VERSION 5.7 ;
BUSBITCHARS "[]" ;
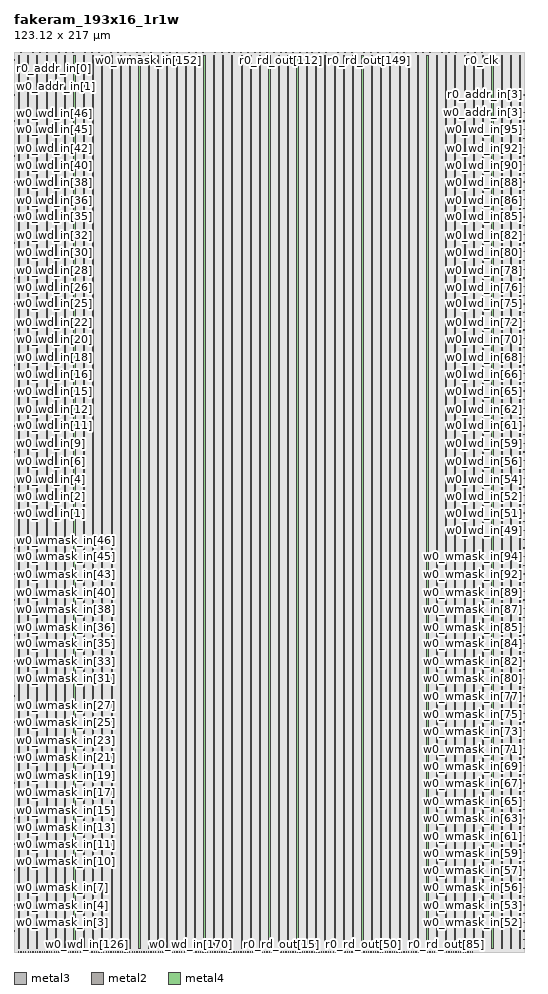
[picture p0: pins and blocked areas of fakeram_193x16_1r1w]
MACRO fakeram_193x16_1r1w
  FOREIGN fakeram_193x16_1r1w 0 0 ;
  SYMMETRY X Y R90 ;
  SIZE 123.120 BY 217.000 ;
  CLASS BLOCK ;
  PIN w0_wmask_in[0]
    DIRECTION INPUT ;
    USE SIGNAL ;
    SHAPE ABUTMENT ;
    PORT
      LAYER metal3 ;
      RECT 0.000 0.805 0.210 0.875 ;
    END
  END w0_wmask_in[0]
  PIN w0_wmask_in[1]
    DIRECTION INPUT ;
    USE SIGNAL ;
    SHAPE ABUTMENT ;
    PORT
      LAYER metal3 ;
      RECT 0.000 2.905 0.210 2.975 ;
    END
  END w0_wmask_in[1]
  PIN w0_wmask_in[2]
    DIRECTION INPUT ;
    USE SIGNAL ;
    SHAPE ABUTMENT ;
    PORT
      LAYER metal3 ;
      RECT 0.000 5.005 0.210 5.075 ;
    END
  END w0_wmask_in[2]
  PIN w0_wmask_in[3]
    DIRECTION INPUT ;
    USE SIGNAL ;
    SHAPE ABUTMENT ;
    PORT
      LAYER metal3 ;
      RECT 0.000 7.105 0.210 7.175 ;
    END
  END w0_wmask_in[3]
  PIN w0_wmask_in[4]
    DIRECTION INPUT ;
    USE SIGNAL ;
    SHAPE ABUTMENT ;
    PORT
      LAYER metal3 ;
      RECT 0.000 9.205 0.210 9.275 ;
    END
  END w0_wmask_in[4]
  PIN w0_wmask_in[5]
    DIRECTION INPUT ;
    USE SIGNAL ;
    SHAPE ABUTMENT ;
    PORT
      LAYER metal3 ;
      RECT 0.000 11.305 0.210 11.375 ;
    END
  END w0_wmask_in[5]
  PIN w0_wmask_in[6]
    DIRECTION INPUT ;
    USE SIGNAL ;
    SHAPE ABUTMENT ;
    PORT
      LAYER metal3 ;
      RECT 0.000 13.405 0.210 13.475 ;
    END
  END w0_wmask_in[6]
  PIN w0_wmask_in[7]
    DIRECTION INPUT ;
    USE SIGNAL ;
    SHAPE ABUTMENT ;
    PORT
      LAYER metal3 ;
      RECT 0.000 15.505 0.210 15.575 ;
    END
  END w0_wmask_in[7]
  PIN w0_wmask_in[8]
    DIRECTION INPUT ;
    USE SIGNAL ;
    SHAPE ABUTMENT ;
    PORT
      LAYER metal3 ;
      RECT 0.000 17.605 0.210 17.675 ;
    END
  END w0_wmask_in[8]
  PIN w0_wmask_in[9]
    DIRECTION INPUT ;
    USE SIGNAL ;
    SHAPE ABUTMENT ;
    PORT
      LAYER metal3 ;
      RECT 0.000 19.705 0.210 19.775 ;
    END
  END w0_wmask_in[9]
  PIN w0_wmask_in[10]
    DIRECTION INPUT ;
    USE SIGNAL ;
    SHAPE ABUTMENT ;
    PORT
      LAYER metal3 ;
      RECT 0.000 21.805 0.210 21.875 ;
    END
  END w0_wmask_in[10]
  PIN w0_wmask_in[11]
    DIRECTION INPUT ;
    USE SIGNAL ;
    SHAPE ABUTMENT ;
    PORT
      LAYER metal3 ;
      RECT 0.000 23.905 0.210 23.975 ;
    END
  END w0_wmask_in[11]
  PIN w0_wmask_in[12]
    DIRECTION INPUT ;
    USE SIGNAL ;
    SHAPE ABUTMENT ;
    PORT
      LAYER metal3 ;
      RECT 0.000 26.005 0.210 26.075 ;
    END
  END w0_wmask_in[12]
  PIN w0_wmask_in[13]
    DIRECTION INPUT ;
    USE SIGNAL ;
    SHAPE ABUTMENT ;
    PORT
      LAYER metal3 ;
      RECT 0.000 28.105 0.210 28.175 ;
    END
  END w0_wmask_in[13]
  PIN w0_wmask_in[14]
    DIRECTION INPUT ;
    USE SIGNAL ;
    SHAPE ABUTMENT ;
    PORT
      LAYER metal3 ;
      RECT 0.000 30.205 0.210 30.275 ;
    END
  END w0_wmask_in[14]
  PIN w0_wmask_in[15]
    DIRECTION INPUT ;
    USE SIGNAL ;
    SHAPE ABUTMENT ;
    PORT
      LAYER metal3 ;
      RECT 0.000 32.305 0.210 32.375 ;
    END
  END w0_wmask_in[15]
  PIN w0_wmask_in[16]
    DIRECTION INPUT ;
    USE SIGNAL ;
    SHAPE ABUTMENT ;
    PORT
      LAYER metal3 ;
      RECT 0.000 34.405 0.210 34.475 ;
    END
  END w0_wmask_in[16]
  PIN w0_wmask_in[17]
    DIRECTION INPUT ;
    USE SIGNAL ;
    SHAPE ABUTMENT ;
    PORT
      LAYER metal3 ;
      RECT 0.000 36.505 0.210 36.575 ;
    END
  END w0_wmask_in[17]
  PIN w0_wmask_in[18]
    DIRECTION INPUT ;
    USE SIGNAL ;
    SHAPE ABUTMENT ;
    PORT
      LAYER metal3 ;
      RECT 0.000 38.605 0.210 38.675 ;
    END
  END w0_wmask_in[18]
  PIN w0_wmask_in[19]
    DIRECTION INPUT ;
    USE SIGNAL ;
    SHAPE ABUTMENT ;
    PORT
      LAYER metal3 ;
      RECT 0.000 40.705 0.210 40.775 ;
    END
  END w0_wmask_in[19]
  PIN w0_wmask_in[20]
    DIRECTION INPUT ;
    USE SIGNAL ;
    SHAPE ABUTMENT ;
    PORT
      LAYER metal3 ;
      RECT 0.000 42.805 0.210 42.875 ;
    END
  END w0_wmask_in[20]
  PIN w0_wmask_in[21]
    DIRECTION INPUT ;
    USE SIGNAL ;
    SHAPE ABUTMENT ;
    PORT
      LAYER metal3 ;
      RECT 0.000 44.905 0.210 44.975 ;
    END
  END w0_wmask_in[21]
  PIN w0_wmask_in[22]
    DIRECTION INPUT ;
    USE SIGNAL ;
    SHAPE ABUTMENT ;
    PORT
      LAYER metal3 ;
      RECT 0.000 47.005 0.210 47.075 ;
    END
  END w0_wmask_in[22]
  PIN w0_wmask_in[23]
    DIRECTION INPUT ;
    USE SIGNAL ;
    SHAPE ABUTMENT ;
    PORT
      LAYER metal3 ;
      RECT 0.000 49.105 0.210 49.175 ;
    END
  END w0_wmask_in[23]
  PIN w0_wmask_in[24]
    DIRECTION INPUT ;
    USE SIGNAL ;
    SHAPE ABUTMENT ;
    PORT
      LAYER metal3 ;
      RECT 0.000 51.205 0.210 51.275 ;
    END
  END w0_wmask_in[24]
  PIN w0_wmask_in[25]
    DIRECTION INPUT ;
    USE SIGNAL ;
    SHAPE ABUTMENT ;
    PORT
      LAYER metal3 ;
      RECT 0.000 53.305 0.210 53.375 ;
    END
  END w0_wmask_in[25]
  PIN w0_wmask_in[26]
    DIRECTION INPUT ;
    USE SIGNAL ;
    SHAPE ABUTMENT ;
    PORT
      LAYER metal3 ;
      RECT 0.000 55.405 0.210 55.475 ;
    END
  END w0_wmask_in[26]
  PIN w0_wmask_in[27]
    DIRECTION INPUT ;
    USE SIGNAL ;
    SHAPE ABUTMENT ;
    PORT
      LAYER metal3 ;
      RECT 0.000 57.505 0.210 57.575 ;
    END
  END w0_wmask_in[27]
  PIN w0_wmask_in[28]
    DIRECTION INPUT ;
    USE SIGNAL ;
    SHAPE ABUTMENT ;
    PORT
      LAYER metal3 ;
      RECT 0.000 59.605 0.210 59.675 ;
    END
  END w0_wmask_in[28]
  PIN w0_wmask_in[29]
    DIRECTION INPUT ;
    USE SIGNAL ;
    SHAPE ABUTMENT ;
    PORT
      LAYER metal3 ;
      RECT 0.000 61.705 0.210 61.775 ;
    END
  END w0_wmask_in[29]
  PIN w0_wmask_in[30]
    DIRECTION INPUT ;
    USE SIGNAL ;
    SHAPE ABUTMENT ;
    PORT
      LAYER metal3 ;
      RECT 0.000 63.805 0.210 63.875 ;
    END
  END w0_wmask_in[30]
  PIN w0_wmask_in[31]
    DIRECTION INPUT ;
    USE SIGNAL ;
    SHAPE ABUTMENT ;
    PORT
      LAYER metal3 ;
      RECT 0.000 65.905 0.210 65.975 ;
    END
  END w0_wmask_in[31]
  PIN w0_wmask_in[32]
    DIRECTION INPUT ;
    USE SIGNAL ;
    SHAPE ABUTMENT ;
    PORT
      LAYER metal3 ;
      RECT 0.000 68.005 0.210 68.075 ;
    END
  END w0_wmask_in[32]
  PIN w0_wmask_in[33]
    DIRECTION INPUT ;
    USE SIGNAL ;
    SHAPE ABUTMENT ;
    PORT
      LAYER metal3 ;
      RECT 0.000 70.105 0.210 70.175 ;
    END
  END w0_wmask_in[33]
  PIN w0_wmask_in[34]
    DIRECTION INPUT ;
    USE SIGNAL ;
    SHAPE ABUTMENT ;
    PORT
      LAYER metal3 ;
      RECT 0.000 72.205 0.210 72.275 ;
    END
  END w0_wmask_in[34]
  PIN w0_wmask_in[35]
    DIRECTION INPUT ;
    USE SIGNAL ;
    SHAPE ABUTMENT ;
    PORT
      LAYER metal3 ;
      RECT 0.000 74.305 0.210 74.375 ;
    END
  END w0_wmask_in[35]
  PIN w0_wmask_in[36]
    DIRECTION INPUT ;
    USE SIGNAL ;
    SHAPE ABUTMENT ;
    PORT
      LAYER metal3 ;
      RECT 0.000 76.405 0.210 76.475 ;
    END
  END w0_wmask_in[36]
  PIN w0_wmask_in[37]
    DIRECTION INPUT ;
    USE SIGNAL ;
    SHAPE ABUTMENT ;
    PORT
      LAYER metal3 ;
      RECT 0.000 78.505 0.210 78.575 ;
    END
  END w0_wmask_in[37]
  PIN w0_wmask_in[38]
    DIRECTION INPUT ;
    USE SIGNAL ;
    SHAPE ABUTMENT ;
    PORT
      LAYER metal3 ;
      RECT 0.000 80.605 0.210 80.675 ;
    END
  END w0_wmask_in[38]
  PIN w0_wmask_in[39]
    DIRECTION INPUT ;
    USE SIGNAL ;
    SHAPE ABUTMENT ;
    PORT
      LAYER metal3 ;
      RECT 0.000 82.705 0.210 82.775 ;
    END
  END w0_wmask_in[39]
  PIN w0_wmask_in[40]
    DIRECTION INPUT ;
    USE SIGNAL ;
    SHAPE ABUTMENT ;
    PORT
      LAYER metal3 ;
      RECT 0.000 84.805 0.210 84.875 ;
    END
  END w0_wmask_in[40]
  PIN w0_wmask_in[41]
    DIRECTION INPUT ;
    USE SIGNAL ;
    SHAPE ABUTMENT ;
    PORT
      LAYER metal3 ;
      RECT 0.000 86.905 0.210 86.975 ;
    END
  END w0_wmask_in[41]
  PIN w0_wmask_in[42]
    DIRECTION INPUT ;
    USE SIGNAL ;
    SHAPE ABUTMENT ;
    PORT
      LAYER metal3 ;
      RECT 0.000 89.005 0.210 89.075 ;
    END
  END w0_wmask_in[42]
  PIN w0_wmask_in[43]
    DIRECTION INPUT ;
    USE SIGNAL ;
    SHAPE ABUTMENT ;
    PORT
      LAYER metal3 ;
      RECT 0.000 91.105 0.210 91.175 ;
    END
  END w0_wmask_in[43]
  PIN w0_wmask_in[44]
    DIRECTION INPUT ;
    USE SIGNAL ;
    SHAPE ABUTMENT ;
    PORT
      LAYER metal3 ;
      RECT 0.000 93.205 0.210 93.275 ;
    END
  END w0_wmask_in[44]
  PIN w0_wmask_in[45]
    DIRECTION INPUT ;
    USE SIGNAL ;
    SHAPE ABUTMENT ;
    PORT
      LAYER metal3 ;
      RECT 0.000 95.305 0.210 95.375 ;
    END
  END w0_wmask_in[45]
  PIN w0_wmask_in[46]
    DIRECTION INPUT ;
    USE SIGNAL ;
    SHAPE ABUTMENT ;
    PORT
      LAYER metal3 ;
      RECT 0.000 97.405 0.210 97.475 ;
    END
  END w0_wmask_in[46]
  PIN w0_wmask_in[47]
    DIRECTION INPUT ;
    USE SIGNAL ;
    SHAPE ABUTMENT ;
    PORT
      LAYER metal3 ;
      RECT 0.000 99.505 0.210 99.575 ;
    END
  END w0_wmask_in[47]
  PIN w0_wmask_in[48]
    DIRECTION INPUT ;
    USE SIGNAL ;
    SHAPE ABUTMENT ;
    PORT
      LAYER metal3 ;
      RECT 0.000 101.605 0.210 101.675 ;
    END
  END w0_wmask_in[48]
  PIN w0_wmask_in[49]
    DIRECTION INPUT ;
    USE SIGNAL ;
    SHAPE ABUTMENT ;
    PORT
      LAYER metal3 ;
      RECT 122.910 0.805 123.120 0.875 ;
    END
  END w0_wmask_in[49]
  PIN w0_wmask_in[50]
    DIRECTION INPUT ;
    USE SIGNAL ;
    SHAPE ABUTMENT ;
    PORT
      LAYER metal3 ;
      RECT 122.910 2.905 123.120 2.975 ;
    END
  END w0_wmask_in[50]
  PIN w0_wmask_in[51]
    DIRECTION INPUT ;
    USE SIGNAL ;
    SHAPE ABUTMENT ;
    PORT
      LAYER metal3 ;
      RECT 122.910 5.005 123.120 5.075 ;
    END
  END w0_wmask_in[51]
  PIN w0_wmask_in[52]
    DIRECTION INPUT ;
    USE SIGNAL ;
    SHAPE ABUTMENT ;
    PORT
      LAYER metal3 ;
      RECT 122.910 7.105 123.120 7.175 ;
    END
  END w0_wmask_in[52]
  PIN w0_wmask_in[53]
    DIRECTION INPUT ;
    USE SIGNAL ;
    SHAPE ABUTMENT ;
    PORT
      LAYER metal3 ;
      RECT 122.910 9.205 123.120 9.275 ;
    END
  END w0_wmask_in[53]
  PIN w0_wmask_in[54]
    DIRECTION INPUT ;
    USE SIGNAL ;
    SHAPE ABUTMENT ;
    PORT
      LAYER metal3 ;
      RECT 122.910 11.305 123.120 11.375 ;
    END
  END w0_wmask_in[54]
  PIN w0_wmask_in[55]
    DIRECTION INPUT ;
    USE SIGNAL ;
    SHAPE ABUTMENT ;
    PORT
      LAYER metal3 ;
      RECT 122.910 13.405 123.120 13.475 ;
    END
  END w0_wmask_in[55]
  PIN w0_wmask_in[56]
    DIRECTION INPUT ;
    USE SIGNAL ;
    SHAPE ABUTMENT ;
    PORT
      LAYER metal3 ;
      RECT 122.910 15.505 123.120 15.575 ;
    END
  END w0_wmask_in[56]
  PIN w0_wmask_in[57]
    DIRECTION INPUT ;
    USE SIGNAL ;
    SHAPE ABUTMENT ;
    PORT
      LAYER metal3 ;
      RECT 122.910 17.605 123.120 17.675 ;
    END
  END w0_wmask_in[57]
  PIN w0_wmask_in[58]
    DIRECTION INPUT ;
    USE SIGNAL ;
    SHAPE ABUTMENT ;
    PORT
      LAYER metal3 ;
      RECT 122.910 19.705 123.120 19.775 ;
    END
  END w0_wmask_in[58]
  PIN w0_wmask_in[59]
    DIRECTION INPUT ;
    USE SIGNAL ;
    SHAPE ABUTMENT ;
    PORT
      LAYER metal3 ;
      RECT 122.910 21.805 123.120 21.875 ;
    END
  END w0_wmask_in[59]
  PIN w0_wmask_in[60]
    DIRECTION INPUT ;
    USE SIGNAL ;
    SHAPE ABUTMENT ;
    PORT
      LAYER metal3 ;
      RECT 122.910 23.905 123.120 23.975 ;
    END
  END w0_wmask_in[60]
  PIN w0_wmask_in[61]
    DIRECTION INPUT ;
    USE SIGNAL ;
    SHAPE ABUTMENT ;
    PORT
      LAYER metal3 ;
      RECT 122.910 26.005 123.120 26.075 ;
    END
  END w0_wmask_in[61]
  PIN w0_wmask_in[62]
    DIRECTION INPUT ;
    USE SIGNAL ;
    SHAPE ABUTMENT ;
    PORT
      LAYER metal3 ;
      RECT 122.910 28.105 123.120 28.175 ;
    END
  END w0_wmask_in[62]
  PIN w0_wmask_in[63]
    DIRECTION INPUT ;
    USE SIGNAL ;
    SHAPE ABUTMENT ;
    PORT
      LAYER metal3 ;
      RECT 122.910 30.205 123.120 30.275 ;
    END
  END w0_wmask_in[63]
  PIN w0_wmask_in[64]
    DIRECTION INPUT ;
    USE SIGNAL ;
    SHAPE ABUTMENT ;
    PORT
      LAYER metal3 ;
      RECT 122.910 32.305 123.120 32.375 ;
    END
  END w0_wmask_in[64]
  PIN w0_wmask_in[65]
    DIRECTION INPUT ;
    USE SIGNAL ;
    SHAPE ABUTMENT ;
    PORT
      LAYER metal3 ;
      RECT 122.910 34.405 123.120 34.475 ;
    END
  END w0_wmask_in[65]
  PIN w0_wmask_in[66]
    DIRECTION INPUT ;
    USE SIGNAL ;
    SHAPE ABUTMENT ;
    PORT
      LAYER metal3 ;
      RECT 122.910 36.505 123.120 36.575 ;
    END
  END w0_wmask_in[66]
  PIN w0_wmask_in[67]
    DIRECTION INPUT ;
    USE SIGNAL ;
    SHAPE ABUTMENT ;
    PORT
      LAYER metal3 ;
      RECT 122.910 38.605 123.120 38.675 ;
    END
  END w0_wmask_in[67]
  PIN w0_wmask_in[68]
    DIRECTION INPUT ;
    USE SIGNAL ;
    SHAPE ABUTMENT ;
    PORT
      LAYER metal3 ;
      RECT 122.910 40.705 123.120 40.775 ;
    END
  END w0_wmask_in[68]
  PIN w0_wmask_in[69]
    DIRECTION INPUT ;
    USE SIGNAL ;
    SHAPE ABUTMENT ;
    PORT
      LAYER metal3 ;
      RECT 122.910 42.805 123.120 42.875 ;
    END
  END w0_wmask_in[69]
  PIN w0_wmask_in[70]
    DIRECTION INPUT ;
    USE SIGNAL ;
    SHAPE ABUTMENT ;
    PORT
      LAYER metal3 ;
      RECT 122.910 44.905 123.120 44.975 ;
    END
  END w0_wmask_in[70]
  PIN w0_wmask_in[71]
    DIRECTION INPUT ;
    USE SIGNAL ;
    SHAPE ABUTMENT ;
    PORT
      LAYER metal3 ;
      RECT 122.910 47.005 123.120 47.075 ;
    END
  END w0_wmask_in[71]
  PIN w0_wmask_in[72]
    DIRECTION INPUT ;
    USE SIGNAL ;
    SHAPE ABUTMENT ;
    PORT
      LAYER metal3 ;
      RECT 122.910 49.105 123.120 49.175 ;
    END
  END w0_wmask_in[72]
  PIN w0_wmask_in[73]
    DIRECTION INPUT ;
    USE SIGNAL ;
    SHAPE ABUTMENT ;
    PORT
      LAYER metal3 ;
      RECT 122.910 51.205 123.120 51.275 ;
    END
  END w0_wmask_in[73]
  PIN w0_wmask_in[74]
    DIRECTION INPUT ;
    USE SIGNAL ;
    SHAPE ABUTMENT ;
    PORT
      LAYER metal3 ;
      RECT 122.910 53.305 123.120 53.375 ;
    END
  END w0_wmask_in[74]
  PIN w0_wmask_in[75]
    DIRECTION INPUT ;
    USE SIGNAL ;
    SHAPE ABUTMENT ;
    PORT
      LAYER metal3 ;
      RECT 122.910 55.405 123.120 55.475 ;
    END
  END w0_wmask_in[75]
  PIN w0_wmask_in[76]
    DIRECTION INPUT ;
    USE SIGNAL ;
    SHAPE ABUTMENT ;
    PORT
      LAYER metal3 ;
      RECT 122.910 57.505 123.120 57.575 ;
    END
  END w0_wmask_in[76]
  PIN w0_wmask_in[77]
    DIRECTION INPUT ;
    USE SIGNAL ;
    SHAPE ABUTMENT ;
    PORT
      LAYER metal3 ;
      RECT 122.910 59.605 123.120 59.675 ;
    END
  END w0_wmask_in[77]
  PIN w0_wmask_in[78]
    DIRECTION INPUT ;
    USE SIGNAL ;
    SHAPE ABUTMENT ;
    PORT
      LAYER metal3 ;
      RECT 122.910 61.705 123.120 61.775 ;
    END
  END w0_wmask_in[78]
  PIN w0_wmask_in[79]
    DIRECTION INPUT ;
    USE SIGNAL ;
    SHAPE ABUTMENT ;
    PORT
      LAYER metal3 ;
      RECT 122.910 63.805 123.120 63.875 ;
    END
  END w0_wmask_in[79]
  PIN w0_wmask_in[80]
    DIRECTION INPUT ;
    USE SIGNAL ;
    SHAPE ABUTMENT ;
    PORT
      LAYER metal3 ;
      RECT 122.910 65.905 123.120 65.975 ;
    END
  END w0_wmask_in[80]
  PIN w0_wmask_in[81]
    DIRECTION INPUT ;
    USE SIGNAL ;
    SHAPE ABUTMENT ;
    PORT
      LAYER metal3 ;
      RECT 122.910 68.005 123.120 68.075 ;
    END
  END w0_wmask_in[81]
  PIN w0_wmask_in[82]
    DIRECTION INPUT ;
    USE SIGNAL ;
    SHAPE ABUTMENT ;
    PORT
      LAYER metal3 ;
      RECT 122.910 70.105 123.120 70.175 ;
    END
  END w0_wmask_in[82]
  PIN w0_wmask_in[83]
    DIRECTION INPUT ;
    USE SIGNAL ;
    SHAPE ABUTMENT ;
    PORT
      LAYER metal3 ;
      RECT 122.910 72.205 123.120 72.275 ;
    END
  END w0_wmask_in[83]
  PIN w0_wmask_in[84]
    DIRECTION INPUT ;
    USE SIGNAL ;
    SHAPE ABUTMENT ;
    PORT
      LAYER metal3 ;
      RECT 122.910 74.305 123.120 74.375 ;
    END
  END w0_wmask_in[84]
  PIN w0_wmask_in[85]
    DIRECTION INPUT ;
    USE SIGNAL ;
    SHAPE ABUTMENT ;
    PORT
      LAYER metal3 ;
      RECT 122.910 76.405 123.120 76.475 ;
    END
  END w0_wmask_in[85]
  PIN w0_wmask_in[86]
    DIRECTION INPUT ;
    USE SIGNAL ;
    SHAPE ABUTMENT ;
    PORT
      LAYER metal3 ;
      RECT 122.910 78.505 123.120 78.575 ;
    END
  END w0_wmask_in[86]
  PIN w0_wmask_in[87]
    DIRECTION INPUT ;
    USE SIGNAL ;
    SHAPE ABUTMENT ;
    PORT
      LAYER metal3 ;
      RECT 122.910 80.605 123.120 80.675 ;
    END
  END w0_wmask_in[87]
  PIN w0_wmask_in[88]
    DIRECTION INPUT ;
    USE SIGNAL ;
    SHAPE ABUTMENT ;
    PORT
      LAYER metal3 ;
      RECT 122.910 82.705 123.120 82.775 ;
    END
  END w0_wmask_in[88]
  PIN w0_wmask_in[89]
    DIRECTION INPUT ;
    USE SIGNAL ;
    SHAPE ABUTMENT ;
    PORT
      LAYER metal3 ;
      RECT 122.910 84.805 123.120 84.875 ;
    END
  END w0_wmask_in[89]
  PIN w0_wmask_in[90]
    DIRECTION INPUT ;
    USE SIGNAL ;
    SHAPE ABUTMENT ;
    PORT
      LAYER metal3 ;
      RECT 122.910 86.905 123.120 86.975 ;
    END
  END w0_wmask_in[90]
  PIN w0_wmask_in[91]
    DIRECTION INPUT ;
    USE SIGNAL ;
    SHAPE ABUTMENT ;
    PORT
      LAYER metal3 ;
      RECT 122.910 89.005 123.120 89.075 ;
    END
  END w0_wmask_in[91]
  PIN w0_wmask_in[92]
    DIRECTION INPUT ;
    USE SIGNAL ;
    SHAPE ABUTMENT ;
    PORT
      LAYER metal3 ;
      RECT 122.910 91.105 123.120 91.175 ;
    END
  END w0_wmask_in[92]
  PIN w0_wmask_in[93]
    DIRECTION INPUT ;
    USE SIGNAL ;
    SHAPE ABUTMENT ;
    PORT
      LAYER metal3 ;
      RECT 122.910 93.205 123.120 93.275 ;
    END
  END w0_wmask_in[93]
  PIN w0_wmask_in[94]
    DIRECTION INPUT ;
    USE SIGNAL ;
    SHAPE ABUTMENT ;
    PORT
      LAYER metal3 ;
      RECT 122.910 95.305 123.120 95.375 ;
    END
  END w0_wmask_in[94]
  PIN w0_wmask_in[95]
    DIRECTION INPUT ;
    USE SIGNAL ;
    SHAPE ABUTMENT ;
    PORT
      LAYER metal3 ;
      RECT 122.910 97.405 123.120 97.475 ;
    END
  END w0_wmask_in[95]
  PIN w0_wmask_in[96]
    DIRECTION INPUT ;
    USE SIGNAL ;
    SHAPE ABUTMENT ;
    PORT
      LAYER metal3 ;
      RECT 122.910 99.505 123.120 99.575 ;
    END
  END w0_wmask_in[96]
  PIN w0_wmask_in[97]
    DIRECTION INPUT ;
    USE SIGNAL ;
    SHAPE ABUTMENT ;
    PORT
      LAYER metal2 ;
      RECT 1.105 216.790 1.175 217.000 ;
    END
  END w0_wmask_in[97]
  PIN w0_wmask_in[98]
    DIRECTION INPUT ;
    USE SIGNAL ;
    SHAPE ABUTMENT ;
    PORT
      LAYER metal2 ;
      RECT 1.675 216.790 1.745 217.000 ;
    END
  END w0_wmask_in[98]
  PIN w0_wmask_in[99]
    DIRECTION INPUT ;
    USE SIGNAL ;
    SHAPE ABUTMENT ;
    PORT
      LAYER metal2 ;
      RECT 2.245 216.790 2.315 217.000 ;
    END
  END w0_wmask_in[99]
  PIN w0_wmask_in[100]
    DIRECTION INPUT ;
    USE SIGNAL ;
    SHAPE ABUTMENT ;
    PORT
      LAYER metal2 ;
      RECT 2.815 216.790 2.885 217.000 ;
    END
  END w0_wmask_in[100]
  PIN w0_wmask_in[101]
    DIRECTION INPUT ;
    USE SIGNAL ;
    SHAPE ABUTMENT ;
    PORT
      LAYER metal2 ;
      RECT 3.385 216.790 3.455 217.000 ;
    END
  END w0_wmask_in[101]
  PIN w0_wmask_in[102]
    DIRECTION INPUT ;
    USE SIGNAL ;
    SHAPE ABUTMENT ;
    PORT
      LAYER metal2 ;
      RECT 3.955 216.790 4.025 217.000 ;
    END
  END w0_wmask_in[102]
  PIN w0_wmask_in[103]
    DIRECTION INPUT ;
    USE SIGNAL ;
    SHAPE ABUTMENT ;
    PORT
      LAYER metal2 ;
      RECT 4.525 216.790 4.595 217.000 ;
    END
  END w0_wmask_in[103]
  PIN w0_wmask_in[104]
    DIRECTION INPUT ;
    USE SIGNAL ;
    SHAPE ABUTMENT ;
    PORT
      LAYER metal2 ;
      RECT 5.095 216.790 5.165 217.000 ;
    END
  END w0_wmask_in[104]
  PIN w0_wmask_in[105]
    DIRECTION INPUT ;
    USE SIGNAL ;
    SHAPE ABUTMENT ;
    PORT
      LAYER metal2 ;
      RECT 5.665 216.790 5.735 217.000 ;
    END
  END w0_wmask_in[105]
  PIN w0_wmask_in[106]
    DIRECTION INPUT ;
    USE SIGNAL ;
    SHAPE ABUTMENT ;
    PORT
      LAYER metal2 ;
      RECT 6.235 216.790 6.305 217.000 ;
    END
  END w0_wmask_in[106]
  PIN w0_wmask_in[107]
    DIRECTION INPUT ;
    USE SIGNAL ;
    SHAPE ABUTMENT ;
    PORT
      LAYER metal2 ;
      RECT 6.805 216.790 6.875 217.000 ;
    END
  END w0_wmask_in[107]
  PIN w0_wmask_in[108]
    DIRECTION INPUT ;
    USE SIGNAL ;
    SHAPE ABUTMENT ;
    PORT
      LAYER metal2 ;
      RECT 7.375 216.790 7.445 217.000 ;
    END
  END w0_wmask_in[108]
  PIN w0_wmask_in[109]
    DIRECTION INPUT ;
    USE SIGNAL ;
    SHAPE ABUTMENT ;
    PORT
      LAYER metal2 ;
      RECT 7.945 216.790 8.015 217.000 ;
    END
  END w0_wmask_in[109]
  PIN w0_wmask_in[110]
    DIRECTION INPUT ;
    USE SIGNAL ;
    SHAPE ABUTMENT ;
    PORT
      LAYER metal2 ;
      RECT 8.515 216.790 8.585 217.000 ;
    END
  END w0_wmask_in[110]
  PIN w0_wmask_in[111]
    DIRECTION INPUT ;
    USE SIGNAL ;
    SHAPE ABUTMENT ;
    PORT
      LAYER metal2 ;
      RECT 9.085 216.790 9.155 217.000 ;
    END
  END w0_wmask_in[111]
  PIN w0_wmask_in[112]
    DIRECTION INPUT ;
    USE SIGNAL ;
    SHAPE ABUTMENT ;
    PORT
      LAYER metal2 ;
      RECT 9.655 216.790 9.725 217.000 ;
    END
  END w0_wmask_in[112]
  PIN w0_wmask_in[113]
    DIRECTION INPUT ;
    USE SIGNAL ;
    SHAPE ABUTMENT ;
    PORT
      LAYER metal2 ;
      RECT 10.225 216.790 10.295 217.000 ;
    END
  END w0_wmask_in[113]
  PIN w0_wmask_in[114]
    DIRECTION INPUT ;
    USE SIGNAL ;
    SHAPE ABUTMENT ;
    PORT
      LAYER metal2 ;
      RECT 10.795 216.790 10.865 217.000 ;
    END
  END w0_wmask_in[114]
  PIN w0_wmask_in[115]
    DIRECTION INPUT ;
    USE SIGNAL ;
    SHAPE ABUTMENT ;
    PORT
      LAYER metal2 ;
      RECT 11.365 216.790 11.435 217.000 ;
    END
  END w0_wmask_in[115]
  PIN w0_wmask_in[116]
    DIRECTION INPUT ;
    USE SIGNAL ;
    SHAPE ABUTMENT ;
    PORT
      LAYER metal2 ;
      RECT 11.935 216.790 12.005 217.000 ;
    END
  END w0_wmask_in[116]
  PIN w0_wmask_in[117]
    DIRECTION INPUT ;
    USE SIGNAL ;
    SHAPE ABUTMENT ;
    PORT
      LAYER metal2 ;
      RECT 12.505 216.790 12.575 217.000 ;
    END
  END w0_wmask_in[117]
  PIN w0_wmask_in[118]
    DIRECTION INPUT ;
    USE SIGNAL ;
    SHAPE ABUTMENT ;
    PORT
      LAYER metal2 ;
      RECT 13.075 216.790 13.145 217.000 ;
    END
  END w0_wmask_in[118]
  PIN w0_wmask_in[119]
    DIRECTION INPUT ;
    USE SIGNAL ;
    SHAPE ABUTMENT ;
    PORT
      LAYER metal2 ;
      RECT 13.645 216.790 13.715 217.000 ;
    END
  END w0_wmask_in[119]
  PIN w0_wmask_in[120]
    DIRECTION INPUT ;
    USE SIGNAL ;
    SHAPE ABUTMENT ;
    PORT
      LAYER metal2 ;
      RECT 14.215 216.790 14.285 217.000 ;
    END
  END w0_wmask_in[120]
  PIN w0_wmask_in[121]
    DIRECTION INPUT ;
    USE SIGNAL ;
    SHAPE ABUTMENT ;
    PORT
      LAYER metal2 ;
      RECT 14.785 216.790 14.855 217.000 ;
    END
  END w0_wmask_in[121]
  PIN w0_wmask_in[122]
    DIRECTION INPUT ;
    USE SIGNAL ;
    SHAPE ABUTMENT ;
    PORT
      LAYER metal2 ;
      RECT 15.355 216.790 15.425 217.000 ;
    END
  END w0_wmask_in[122]
  PIN w0_wmask_in[123]
    DIRECTION INPUT ;
    USE SIGNAL ;
    SHAPE ABUTMENT ;
    PORT
      LAYER metal2 ;
      RECT 15.925 216.790 15.995 217.000 ;
    END
  END w0_wmask_in[123]
  PIN w0_wmask_in[124]
    DIRECTION INPUT ;
    USE SIGNAL ;
    SHAPE ABUTMENT ;
    PORT
      LAYER metal2 ;
      RECT 16.495 216.790 16.565 217.000 ;
    END
  END w0_wmask_in[124]
  PIN w0_wmask_in[125]
    DIRECTION INPUT ;
    USE SIGNAL ;
    SHAPE ABUTMENT ;
    PORT
      LAYER metal2 ;
      RECT 17.065 216.790 17.135 217.000 ;
    END
  END w0_wmask_in[125]
  PIN w0_wmask_in[126]
    DIRECTION INPUT ;
    USE SIGNAL ;
    SHAPE ABUTMENT ;
    PORT
      LAYER metal2 ;
      RECT 17.635 216.790 17.705 217.000 ;
    END
  END w0_wmask_in[126]
  PIN w0_wmask_in[127]
    DIRECTION INPUT ;
    USE SIGNAL ;
    SHAPE ABUTMENT ;
    PORT
      LAYER metal2 ;
      RECT 18.205 216.790 18.275 217.000 ;
    END
  END w0_wmask_in[127]
  PIN w0_wmask_in[128]
    DIRECTION INPUT ;
    USE SIGNAL ;
    SHAPE ABUTMENT ;
    PORT
      LAYER metal2 ;
      RECT 18.775 216.790 18.845 217.000 ;
    END
  END w0_wmask_in[128]
  PIN w0_wmask_in[129]
    DIRECTION INPUT ;
    USE SIGNAL ;
    SHAPE ABUTMENT ;
    PORT
      LAYER metal2 ;
      RECT 19.345 216.790 19.415 217.000 ;
    END
  END w0_wmask_in[129]
  PIN w0_wmask_in[130]
    DIRECTION INPUT ;
    USE SIGNAL ;
    SHAPE ABUTMENT ;
    PORT
      LAYER metal2 ;
      RECT 19.915 216.790 19.985 217.000 ;
    END
  END w0_wmask_in[130]
  PIN w0_wmask_in[131]
    DIRECTION INPUT ;
    USE SIGNAL ;
    SHAPE ABUTMENT ;
    PORT
      LAYER metal2 ;
      RECT 20.485 216.790 20.555 217.000 ;
    END
  END w0_wmask_in[131]
  PIN w0_wmask_in[132]
    DIRECTION INPUT ;
    USE SIGNAL ;
    SHAPE ABUTMENT ;
    PORT
      LAYER metal2 ;
      RECT 21.055 216.790 21.125 217.000 ;
    END
  END w0_wmask_in[132]
  PIN w0_wmask_in[133]
    DIRECTION INPUT ;
    USE SIGNAL ;
    SHAPE ABUTMENT ;
    PORT
      LAYER metal2 ;
      RECT 21.625 216.790 21.695 217.000 ;
    END
  END w0_wmask_in[133]
  PIN w0_wmask_in[134]
    DIRECTION INPUT ;
    USE SIGNAL ;
    SHAPE ABUTMENT ;
    PORT
      LAYER metal2 ;
      RECT 22.195 216.790 22.265 217.000 ;
    END
  END w0_wmask_in[134]
  PIN w0_wmask_in[135]
    DIRECTION INPUT ;
    USE SIGNAL ;
    SHAPE ABUTMENT ;
    PORT
      LAYER metal2 ;
      RECT 22.765 216.790 22.835 217.000 ;
    END
  END w0_wmask_in[135]
  PIN w0_wmask_in[136]
    DIRECTION INPUT ;
    USE SIGNAL ;
    SHAPE ABUTMENT ;
    PORT
      LAYER metal2 ;
      RECT 23.335 216.790 23.405 217.000 ;
    END
  END w0_wmask_in[136]
  PIN w0_wmask_in[137]
    DIRECTION INPUT ;
    USE SIGNAL ;
    SHAPE ABUTMENT ;
    PORT
      LAYER metal2 ;
      RECT 23.905 216.790 23.975 217.000 ;
    END
  END w0_wmask_in[137]
  PIN w0_wmask_in[138]
    DIRECTION INPUT ;
    USE SIGNAL ;
    SHAPE ABUTMENT ;
    PORT
      LAYER metal2 ;
      RECT 24.475 216.790 24.545 217.000 ;
    END
  END w0_wmask_in[138]
  PIN w0_wmask_in[139]
    DIRECTION INPUT ;
    USE SIGNAL ;
    SHAPE ABUTMENT ;
    PORT
      LAYER metal2 ;
      RECT 25.045 216.790 25.115 217.000 ;
    END
  END w0_wmask_in[139]
  PIN w0_wmask_in[140]
    DIRECTION INPUT ;
    USE SIGNAL ;
    SHAPE ABUTMENT ;
    PORT
      LAYER metal2 ;
      RECT 25.615 216.790 25.685 217.000 ;
    END
  END w0_wmask_in[140]
  PIN w0_wmask_in[141]
    DIRECTION INPUT ;
    USE SIGNAL ;
    SHAPE ABUTMENT ;
    PORT
      LAYER metal2 ;
      RECT 26.185 216.790 26.255 217.000 ;
    END
  END w0_wmask_in[141]
  PIN w0_wmask_in[142]
    DIRECTION INPUT ;
    USE SIGNAL ;
    SHAPE ABUTMENT ;
    PORT
      LAYER metal2 ;
      RECT 26.755 216.790 26.825 217.000 ;
    END
  END w0_wmask_in[142]
  PIN w0_wmask_in[143]
    DIRECTION INPUT ;
    USE SIGNAL ;
    SHAPE ABUTMENT ;
    PORT
      LAYER metal2 ;
      RECT 27.325 216.790 27.395 217.000 ;
    END
  END w0_wmask_in[143]
  PIN w0_wmask_in[144]
    DIRECTION INPUT ;
    USE SIGNAL ;
    SHAPE ABUTMENT ;
    PORT
      LAYER metal2 ;
      RECT 27.895 216.790 27.965 217.000 ;
    END
  END w0_wmask_in[144]
  PIN w0_wmask_in[145]
    DIRECTION INPUT ;
    USE SIGNAL ;
    SHAPE ABUTMENT ;
    PORT
      LAYER metal2 ;
      RECT 28.465 216.790 28.535 217.000 ;
    END
  END w0_wmask_in[145]
  PIN w0_wmask_in[146]
    DIRECTION INPUT ;
    USE SIGNAL ;
    SHAPE ABUTMENT ;
    PORT
      LAYER metal2 ;
      RECT 29.035 216.790 29.105 217.000 ;
    END
  END w0_wmask_in[146]
  PIN w0_wmask_in[147]
    DIRECTION INPUT ;
    USE SIGNAL ;
    SHAPE ABUTMENT ;
    PORT
      LAYER metal2 ;
      RECT 29.605 216.790 29.675 217.000 ;
    END
  END w0_wmask_in[147]
  PIN w0_wmask_in[148]
    DIRECTION INPUT ;
    USE SIGNAL ;
    SHAPE ABUTMENT ;
    PORT
      LAYER metal2 ;
      RECT 30.175 216.790 30.245 217.000 ;
    END
  END w0_wmask_in[148]
  PIN w0_wmask_in[149]
    DIRECTION INPUT ;
    USE SIGNAL ;
    SHAPE ABUTMENT ;
    PORT
      LAYER metal2 ;
      RECT 30.745 216.790 30.815 217.000 ;
    END
  END w0_wmask_in[149]
  PIN w0_wmask_in[150]
    DIRECTION INPUT ;
    USE SIGNAL ;
    SHAPE ABUTMENT ;
    PORT
      LAYER metal2 ;
      RECT 31.315 216.790 31.385 217.000 ;
    END
  END w0_wmask_in[150]
  PIN w0_wmask_in[151]
    DIRECTION INPUT ;
    USE SIGNAL ;
    SHAPE ABUTMENT ;
    PORT
      LAYER metal2 ;
      RECT 31.885 216.790 31.955 217.000 ;
    END
  END w0_wmask_in[151]
  PIN w0_wmask_in[152]
    DIRECTION INPUT ;
    USE SIGNAL ;
    SHAPE ABUTMENT ;
    PORT
      LAYER metal2 ;
      RECT 32.455 216.790 32.525 217.000 ;
    END
  END w0_wmask_in[152]
  PIN w0_wmask_in[153]
    DIRECTION INPUT ;
    USE SIGNAL ;
    SHAPE ABUTMENT ;
    PORT
      LAYER metal2 ;
      RECT 33.025 216.790 33.095 217.000 ;
    END
  END w0_wmask_in[153]
  PIN w0_wmask_in[154]
    DIRECTION INPUT ;
    USE SIGNAL ;
    SHAPE ABUTMENT ;
    PORT
      LAYER metal2 ;
      RECT 33.595 216.790 33.665 217.000 ;
    END
  END w0_wmask_in[154]
  PIN w0_wmask_in[155]
    DIRECTION INPUT ;
    USE SIGNAL ;
    SHAPE ABUTMENT ;
    PORT
      LAYER metal2 ;
      RECT 34.165 216.790 34.235 217.000 ;
    END
  END w0_wmask_in[155]
  PIN w0_wmask_in[156]
    DIRECTION INPUT ;
    USE SIGNAL ;
    SHAPE ABUTMENT ;
    PORT
      LAYER metal2 ;
      RECT 34.735 216.790 34.805 217.000 ;
    END
  END w0_wmask_in[156]
  PIN w0_wmask_in[157]
    DIRECTION INPUT ;
    USE SIGNAL ;
    SHAPE ABUTMENT ;
    PORT
      LAYER metal2 ;
      RECT 35.305 216.790 35.375 217.000 ;
    END
  END w0_wmask_in[157]
  PIN w0_wmask_in[158]
    DIRECTION INPUT ;
    USE SIGNAL ;
    SHAPE ABUTMENT ;
    PORT
      LAYER metal2 ;
      RECT 35.875 216.790 35.945 217.000 ;
    END
  END w0_wmask_in[158]
  PIN w0_wmask_in[159]
    DIRECTION INPUT ;
    USE SIGNAL ;
    SHAPE ABUTMENT ;
    PORT
      LAYER metal2 ;
      RECT 36.445 216.790 36.515 217.000 ;
    END
  END w0_wmask_in[159]
  PIN w0_wmask_in[160]
    DIRECTION INPUT ;
    USE SIGNAL ;
    SHAPE ABUTMENT ;
    PORT
      LAYER metal2 ;
      RECT 37.015 216.790 37.085 217.000 ;
    END
  END w0_wmask_in[160]
  PIN w0_wmask_in[161]
    DIRECTION INPUT ;
    USE SIGNAL ;
    SHAPE ABUTMENT ;
    PORT
      LAYER metal2 ;
      RECT 37.585 216.790 37.655 217.000 ;
    END
  END w0_wmask_in[161]
  PIN w0_wmask_in[162]
    DIRECTION INPUT ;
    USE SIGNAL ;
    SHAPE ABUTMENT ;
    PORT
      LAYER metal2 ;
      RECT 38.155 216.790 38.225 217.000 ;
    END
  END w0_wmask_in[162]
  PIN w0_wmask_in[163]
    DIRECTION INPUT ;
    USE SIGNAL ;
    SHAPE ABUTMENT ;
    PORT
      LAYER metal2 ;
      RECT 38.725 216.790 38.795 217.000 ;
    END
  END w0_wmask_in[163]
  PIN w0_wmask_in[164]
    DIRECTION INPUT ;
    USE SIGNAL ;
    SHAPE ABUTMENT ;
    PORT
      LAYER metal2 ;
      RECT 39.295 216.790 39.365 217.000 ;
    END
  END w0_wmask_in[164]
  PIN w0_wmask_in[165]
    DIRECTION INPUT ;
    USE SIGNAL ;
    SHAPE ABUTMENT ;
    PORT
      LAYER metal2 ;
      RECT 39.865 216.790 39.935 217.000 ;
    END
  END w0_wmask_in[165]
  PIN w0_wmask_in[166]
    DIRECTION INPUT ;
    USE SIGNAL ;
    SHAPE ABUTMENT ;
    PORT
      LAYER metal2 ;
      RECT 40.435 216.790 40.505 217.000 ;
    END
  END w0_wmask_in[166]
  PIN w0_wmask_in[167]
    DIRECTION INPUT ;
    USE SIGNAL ;
    SHAPE ABUTMENT ;
    PORT
      LAYER metal2 ;
      RECT 41.005 216.790 41.075 217.000 ;
    END
  END w0_wmask_in[167]
  PIN w0_wmask_in[168]
    DIRECTION INPUT ;
    USE SIGNAL ;
    SHAPE ABUTMENT ;
    PORT
      LAYER metal2 ;
      RECT 41.575 216.790 41.645 217.000 ;
    END
  END w0_wmask_in[168]
  PIN w0_wmask_in[169]
    DIRECTION INPUT ;
    USE SIGNAL ;
    SHAPE ABUTMENT ;
    PORT
      LAYER metal2 ;
      RECT 42.145 216.790 42.215 217.000 ;
    END
  END w0_wmask_in[169]
  PIN w0_wmask_in[170]
    DIRECTION INPUT ;
    USE SIGNAL ;
    SHAPE ABUTMENT ;
    PORT
      LAYER metal2 ;
      RECT 42.715 216.790 42.785 217.000 ;
    END
  END w0_wmask_in[170]
  PIN w0_wmask_in[171]
    DIRECTION INPUT ;
    USE SIGNAL ;
    SHAPE ABUTMENT ;
    PORT
      LAYER metal2 ;
      RECT 43.285 216.790 43.355 217.000 ;
    END
  END w0_wmask_in[171]
  PIN w0_wmask_in[172]
    DIRECTION INPUT ;
    USE SIGNAL ;
    SHAPE ABUTMENT ;
    PORT
      LAYER metal2 ;
      RECT 43.855 216.790 43.925 217.000 ;
    END
  END w0_wmask_in[172]
  PIN w0_wmask_in[173]
    DIRECTION INPUT ;
    USE SIGNAL ;
    SHAPE ABUTMENT ;
    PORT
      LAYER metal2 ;
      RECT 44.425 216.790 44.495 217.000 ;
    END
  END w0_wmask_in[173]
  PIN w0_wmask_in[174]
    DIRECTION INPUT ;
    USE SIGNAL ;
    SHAPE ABUTMENT ;
    PORT
      LAYER metal2 ;
      RECT 44.995 216.790 45.065 217.000 ;
    END
  END w0_wmask_in[174]
  PIN w0_wmask_in[175]
    DIRECTION INPUT ;
    USE SIGNAL ;
    SHAPE ABUTMENT ;
    PORT
      LAYER metal2 ;
      RECT 45.565 216.790 45.635 217.000 ;
    END
  END w0_wmask_in[175]
  PIN w0_wmask_in[176]
    DIRECTION INPUT ;
    USE SIGNAL ;
    SHAPE ABUTMENT ;
    PORT
      LAYER metal2 ;
      RECT 46.135 216.790 46.205 217.000 ;
    END
  END w0_wmask_in[176]
  PIN w0_wmask_in[177]
    DIRECTION INPUT ;
    USE SIGNAL ;
    SHAPE ABUTMENT ;
    PORT
      LAYER metal2 ;
      RECT 46.705 216.790 46.775 217.000 ;
    END
  END w0_wmask_in[177]
  PIN w0_wmask_in[178]
    DIRECTION INPUT ;
    USE SIGNAL ;
    SHAPE ABUTMENT ;
    PORT
      LAYER metal2 ;
      RECT 47.275 216.790 47.345 217.000 ;
    END
  END w0_wmask_in[178]
  PIN w0_wmask_in[179]
    DIRECTION INPUT ;
    USE SIGNAL ;
    SHAPE ABUTMENT ;
    PORT
      LAYER metal2 ;
      RECT 47.845 216.790 47.915 217.000 ;
    END
  END w0_wmask_in[179]
  PIN w0_wmask_in[180]
    DIRECTION INPUT ;
    USE SIGNAL ;
    SHAPE ABUTMENT ;
    PORT
      LAYER metal2 ;
      RECT 48.415 216.790 48.485 217.000 ;
    END
  END w0_wmask_in[180]
  PIN w0_wmask_in[181]
    DIRECTION INPUT ;
    USE SIGNAL ;
    SHAPE ABUTMENT ;
    PORT
      LAYER metal2 ;
      RECT 48.985 216.790 49.055 217.000 ;
    END
  END w0_wmask_in[181]
  PIN w0_wmask_in[182]
    DIRECTION INPUT ;
    USE SIGNAL ;
    SHAPE ABUTMENT ;
    PORT
      LAYER metal2 ;
      RECT 49.555 216.790 49.625 217.000 ;
    END
  END w0_wmask_in[182]
  PIN w0_wmask_in[183]
    DIRECTION INPUT ;
    USE SIGNAL ;
    SHAPE ABUTMENT ;
    PORT
      LAYER metal2 ;
      RECT 50.125 216.790 50.195 217.000 ;
    END
  END w0_wmask_in[183]
  PIN w0_wmask_in[184]
    DIRECTION INPUT ;
    USE SIGNAL ;
    SHAPE ABUTMENT ;
    PORT
      LAYER metal2 ;
      RECT 50.695 216.790 50.765 217.000 ;
    END
  END w0_wmask_in[184]
  PIN w0_wmask_in[185]
    DIRECTION INPUT ;
    USE SIGNAL ;
    SHAPE ABUTMENT ;
    PORT
      LAYER metal2 ;
      RECT 51.265 216.790 51.335 217.000 ;
    END
  END w0_wmask_in[185]
  PIN w0_wmask_in[186]
    DIRECTION INPUT ;
    USE SIGNAL ;
    SHAPE ABUTMENT ;
    PORT
      LAYER metal2 ;
      RECT 51.835 216.790 51.905 217.000 ;
    END
  END w0_wmask_in[186]
  PIN w0_wmask_in[187]
    DIRECTION INPUT ;
    USE SIGNAL ;
    SHAPE ABUTMENT ;
    PORT
      LAYER metal2 ;
      RECT 52.405 216.790 52.475 217.000 ;
    END
  END w0_wmask_in[187]
  PIN w0_wmask_in[188]
    DIRECTION INPUT ;
    USE SIGNAL ;
    SHAPE ABUTMENT ;
    PORT
      LAYER metal2 ;
      RECT 52.975 216.790 53.045 217.000 ;
    END
  END w0_wmask_in[188]
  PIN w0_wmask_in[189]
    DIRECTION INPUT ;
    USE SIGNAL ;
    SHAPE ABUTMENT ;
    PORT
      LAYER metal2 ;
      RECT 53.545 216.790 53.615 217.000 ;
    END
  END w0_wmask_in[189]
  PIN w0_wmask_in[190]
    DIRECTION INPUT ;
    USE SIGNAL ;
    SHAPE ABUTMENT ;
    PORT
      LAYER metal2 ;
      RECT 54.115 216.790 54.185 217.000 ;
    END
  END w0_wmask_in[190]
  PIN w0_wmask_in[191]
    DIRECTION INPUT ;
    USE SIGNAL ;
    SHAPE ABUTMENT ;
    PORT
      LAYER metal2 ;
      RECT 54.685 216.790 54.755 217.000 ;
    END
  END w0_wmask_in[191]
  PIN w0_wmask_in[192]
    DIRECTION INPUT ;
    USE SIGNAL ;
    SHAPE ABUTMENT ;
    PORT
      LAYER metal2 ;
      RECT 55.255 216.790 55.325 217.000 ;
    END
  END w0_wmask_in[192]
  PIN w0_wd_in[0]
    DIRECTION INPUT ;
    USE SIGNAL ;
    SHAPE ABUTMENT ;
    PORT
      LAYER metal3 ;
      RECT 0.000 103.705 0.210 103.775 ;
    END
  END w0_wd_in[0]
  PIN w0_wd_in[1]
    DIRECTION INPUT ;
    USE SIGNAL ;
    SHAPE ABUTMENT ;
    PORT
      LAYER metal3 ;
      RECT 0.000 105.805 0.210 105.875 ;
    END
  END w0_wd_in[1]
  PIN w0_wd_in[2]
    DIRECTION INPUT ;
    USE SIGNAL ;
    SHAPE ABUTMENT ;
    PORT
      LAYER metal3 ;
      RECT 0.000 107.905 0.210 107.975 ;
    END
  END w0_wd_in[2]
  PIN w0_wd_in[3]
    DIRECTION INPUT ;
    USE SIGNAL ;
    SHAPE ABUTMENT ;
    PORT
      LAYER metal3 ;
      RECT 0.000 110.005 0.210 110.075 ;
    END
  END w0_wd_in[3]
  PIN w0_wd_in[4]
    DIRECTION INPUT ;
    USE SIGNAL ;
    SHAPE ABUTMENT ;
    PORT
      LAYER metal3 ;
      RECT 0.000 112.105 0.210 112.175 ;
    END
  END w0_wd_in[4]
  PIN w0_wd_in[5]
    DIRECTION INPUT ;
    USE SIGNAL ;
    SHAPE ABUTMENT ;
    PORT
      LAYER metal3 ;
      RECT 0.000 114.205 0.210 114.275 ;
    END
  END w0_wd_in[5]
  PIN w0_wd_in[6]
    DIRECTION INPUT ;
    USE SIGNAL ;
    SHAPE ABUTMENT ;
    PORT
      LAYER metal3 ;
      RECT 0.000 116.305 0.210 116.375 ;
    END
  END w0_wd_in[6]
  PIN w0_wd_in[7]
    DIRECTION INPUT ;
    USE SIGNAL ;
    SHAPE ABUTMENT ;
    PORT
      LAYER metal3 ;
      RECT 0.000 118.405 0.210 118.475 ;
    END
  END w0_wd_in[7]
  PIN w0_wd_in[8]
    DIRECTION INPUT ;
    USE SIGNAL ;
    SHAPE ABUTMENT ;
    PORT
      LAYER metal3 ;
      RECT 0.000 120.505 0.210 120.575 ;
    END
  END w0_wd_in[8]
  PIN w0_wd_in[9]
    DIRECTION INPUT ;
    USE SIGNAL ;
    SHAPE ABUTMENT ;
    PORT
      LAYER metal3 ;
      RECT 0.000 122.605 0.210 122.675 ;
    END
  END w0_wd_in[9]
  PIN w0_wd_in[10]
    DIRECTION INPUT ;
    USE SIGNAL ;
    SHAPE ABUTMENT ;
    PORT
      LAYER metal3 ;
      RECT 0.000 124.705 0.210 124.775 ;
    END
  END w0_wd_in[10]
  PIN w0_wd_in[11]
    DIRECTION INPUT ;
    USE SIGNAL ;
    SHAPE ABUTMENT ;
    PORT
      LAYER metal3 ;
      RECT 0.000 126.805 0.210 126.875 ;
    END
  END w0_wd_in[11]
  PIN w0_wd_in[12]
    DIRECTION INPUT ;
    USE SIGNAL ;
    SHAPE ABUTMENT ;
    PORT
      LAYER metal3 ;
      RECT 0.000 128.905 0.210 128.975 ;
    END
  END w0_wd_in[12]
  PIN w0_wd_in[13]
    DIRECTION INPUT ;
    USE SIGNAL ;
    SHAPE ABUTMENT ;
    PORT
      LAYER metal3 ;
      RECT 0.000 131.005 0.210 131.075 ;
    END
  END w0_wd_in[13]
  PIN w0_wd_in[14]
    DIRECTION INPUT ;
    USE SIGNAL ;
    SHAPE ABUTMENT ;
    PORT
      LAYER metal3 ;
      RECT 0.000 133.105 0.210 133.175 ;
    END
  END w0_wd_in[14]
  PIN w0_wd_in[15]
    DIRECTION INPUT ;
    USE SIGNAL ;
    SHAPE ABUTMENT ;
    PORT
      LAYER metal3 ;
      RECT 0.000 135.205 0.210 135.275 ;
    END
  END w0_wd_in[15]
  PIN w0_wd_in[16]
    DIRECTION INPUT ;
    USE SIGNAL ;
    SHAPE ABUTMENT ;
    PORT
      LAYER metal3 ;
      RECT 0.000 137.305 0.210 137.375 ;
    END
  END w0_wd_in[16]
  PIN w0_wd_in[17]
    DIRECTION INPUT ;
    USE SIGNAL ;
    SHAPE ABUTMENT ;
    PORT
      LAYER metal3 ;
      RECT 0.000 139.405 0.210 139.475 ;
    END
  END w0_wd_in[17]
  PIN w0_wd_in[18]
    DIRECTION INPUT ;
    USE SIGNAL ;
    SHAPE ABUTMENT ;
    PORT
      LAYER metal3 ;
      RECT 0.000 141.505 0.210 141.575 ;
    END
  END w0_wd_in[18]
  PIN w0_wd_in[19]
    DIRECTION INPUT ;
    USE SIGNAL ;
    SHAPE ABUTMENT ;
    PORT
      LAYER metal3 ;
      RECT 0.000 143.605 0.210 143.675 ;
    END
  END w0_wd_in[19]
  PIN w0_wd_in[20]
    DIRECTION INPUT ;
    USE SIGNAL ;
    SHAPE ABUTMENT ;
    PORT
      LAYER metal3 ;
      RECT 0.000 145.705 0.210 145.775 ;
    END
  END w0_wd_in[20]
  PIN w0_wd_in[21]
    DIRECTION INPUT ;
    USE SIGNAL ;
    SHAPE ABUTMENT ;
    PORT
      LAYER metal3 ;
      RECT 0.000 147.805 0.210 147.875 ;
    END
  END w0_wd_in[21]
  PIN w0_wd_in[22]
    DIRECTION INPUT ;
    USE SIGNAL ;
    SHAPE ABUTMENT ;
    PORT
      LAYER metal3 ;
      RECT 0.000 149.905 0.210 149.975 ;
    END
  END w0_wd_in[22]
  PIN w0_wd_in[23]
    DIRECTION INPUT ;
    USE SIGNAL ;
    SHAPE ABUTMENT ;
    PORT
      LAYER metal3 ;
      RECT 0.000 152.005 0.210 152.075 ;
    END
  END w0_wd_in[23]
  PIN w0_wd_in[24]
    DIRECTION INPUT ;
    USE SIGNAL ;
    SHAPE ABUTMENT ;
    PORT
      LAYER metal3 ;
      RECT 0.000 154.105 0.210 154.175 ;
    END
  END w0_wd_in[24]
  PIN w0_wd_in[25]
    DIRECTION INPUT ;
    USE SIGNAL ;
    SHAPE ABUTMENT ;
    PORT
      LAYER metal3 ;
      RECT 0.000 156.205 0.210 156.275 ;
    END
  END w0_wd_in[25]
  PIN w0_wd_in[26]
    DIRECTION INPUT ;
    USE SIGNAL ;
    SHAPE ABUTMENT ;
    PORT
      LAYER metal3 ;
      RECT 0.000 158.305 0.210 158.375 ;
    END
  END w0_wd_in[26]
  PIN w0_wd_in[27]
    DIRECTION INPUT ;
    USE SIGNAL ;
    SHAPE ABUTMENT ;
    PORT
      LAYER metal3 ;
      RECT 0.000 160.405 0.210 160.475 ;
    END
  END w0_wd_in[27]
  PIN w0_wd_in[28]
    DIRECTION INPUT ;
    USE SIGNAL ;
    SHAPE ABUTMENT ;
    PORT
      LAYER metal3 ;
      RECT 0.000 162.505 0.210 162.575 ;
    END
  END w0_wd_in[28]
  PIN w0_wd_in[29]
    DIRECTION INPUT ;
    USE SIGNAL ;
    SHAPE ABUTMENT ;
    PORT
      LAYER metal3 ;
      RECT 0.000 164.605 0.210 164.675 ;
    END
  END w0_wd_in[29]
  PIN w0_wd_in[30]
    DIRECTION INPUT ;
    USE SIGNAL ;
    SHAPE ABUTMENT ;
    PORT
      LAYER metal3 ;
      RECT 0.000 166.705 0.210 166.775 ;
    END
  END w0_wd_in[30]
  PIN w0_wd_in[31]
    DIRECTION INPUT ;
    USE SIGNAL ;
    SHAPE ABUTMENT ;
    PORT
      LAYER metal3 ;
      RECT 0.000 168.805 0.210 168.875 ;
    END
  END w0_wd_in[31]
  PIN w0_wd_in[32]
    DIRECTION INPUT ;
    USE SIGNAL ;
    SHAPE ABUTMENT ;
    PORT
      LAYER metal3 ;
      RECT 0.000 170.905 0.210 170.975 ;
    END
  END w0_wd_in[32]
  PIN w0_wd_in[33]
    DIRECTION INPUT ;
    USE SIGNAL ;
    SHAPE ABUTMENT ;
    PORT
      LAYER metal3 ;
      RECT 0.000 173.005 0.210 173.075 ;
    END
  END w0_wd_in[33]
  PIN w0_wd_in[34]
    DIRECTION INPUT ;
    USE SIGNAL ;
    SHAPE ABUTMENT ;
    PORT
      LAYER metal3 ;
      RECT 0.000 175.105 0.210 175.175 ;
    END
  END w0_wd_in[34]
  PIN w0_wd_in[35]
    DIRECTION INPUT ;
    USE SIGNAL ;
    SHAPE ABUTMENT ;
    PORT
      LAYER metal3 ;
      RECT 0.000 177.205 0.210 177.275 ;
    END
  END w0_wd_in[35]
  PIN w0_wd_in[36]
    DIRECTION INPUT ;
    USE SIGNAL ;
    SHAPE ABUTMENT ;
    PORT
      LAYER metal3 ;
      RECT 0.000 179.305 0.210 179.375 ;
    END
  END w0_wd_in[36]
  PIN w0_wd_in[37]
    DIRECTION INPUT ;
    USE SIGNAL ;
    SHAPE ABUTMENT ;
    PORT
      LAYER metal3 ;
      RECT 0.000 181.405 0.210 181.475 ;
    END
  END w0_wd_in[37]
  PIN w0_wd_in[38]
    DIRECTION INPUT ;
    USE SIGNAL ;
    SHAPE ABUTMENT ;
    PORT
      LAYER metal3 ;
      RECT 0.000 183.505 0.210 183.575 ;
    END
  END w0_wd_in[38]
  PIN w0_wd_in[39]
    DIRECTION INPUT ;
    USE SIGNAL ;
    SHAPE ABUTMENT ;
    PORT
      LAYER metal3 ;
      RECT 0.000 185.605 0.210 185.675 ;
    END
  END w0_wd_in[39]
  PIN w0_wd_in[40]
    DIRECTION INPUT ;
    USE SIGNAL ;
    SHAPE ABUTMENT ;
    PORT
      LAYER metal3 ;
      RECT 0.000 187.705 0.210 187.775 ;
    END
  END w0_wd_in[40]
  PIN w0_wd_in[41]
    DIRECTION INPUT ;
    USE SIGNAL ;
    SHAPE ABUTMENT ;
    PORT
      LAYER metal3 ;
      RECT 0.000 189.805 0.210 189.875 ;
    END
  END w0_wd_in[41]
  PIN w0_wd_in[42]
    DIRECTION INPUT ;
    USE SIGNAL ;
    SHAPE ABUTMENT ;
    PORT
      LAYER metal3 ;
      RECT 0.000 191.905 0.210 191.975 ;
    END
  END w0_wd_in[42]
  PIN w0_wd_in[43]
    DIRECTION INPUT ;
    USE SIGNAL ;
    SHAPE ABUTMENT ;
    PORT
      LAYER metal3 ;
      RECT 0.000 194.005 0.210 194.075 ;
    END
  END w0_wd_in[43]
  PIN w0_wd_in[44]
    DIRECTION INPUT ;
    USE SIGNAL ;
    SHAPE ABUTMENT ;
    PORT
      LAYER metal3 ;
      RECT 0.000 196.105 0.210 196.175 ;
    END
  END w0_wd_in[44]
  PIN w0_wd_in[45]
    DIRECTION INPUT ;
    USE SIGNAL ;
    SHAPE ABUTMENT ;
    PORT
      LAYER metal3 ;
      RECT 0.000 198.205 0.210 198.275 ;
    END
  END w0_wd_in[45]
  PIN w0_wd_in[46]
    DIRECTION INPUT ;
    USE SIGNAL ;
    SHAPE ABUTMENT ;
    PORT
      LAYER metal3 ;
      RECT 0.000 200.305 0.210 200.375 ;
    END
  END w0_wd_in[46]
  PIN w0_wd_in[47]
    DIRECTION INPUT ;
    USE SIGNAL ;
    SHAPE ABUTMENT ;
    PORT
      LAYER metal3 ;
      RECT 0.000 202.405 0.210 202.475 ;
    END
  END w0_wd_in[47]
  PIN w0_wd_in[48]
    DIRECTION INPUT ;
    USE SIGNAL ;
    SHAPE ABUTMENT ;
    PORT
      LAYER metal3 ;
      RECT 0.000 204.505 0.210 204.575 ;
    END
  END w0_wd_in[48]
  PIN w0_wd_in[49]
    DIRECTION INPUT ;
    USE SIGNAL ;
    SHAPE ABUTMENT ;
    PORT
      LAYER metal3 ;
      RECT 122.910 101.605 123.120 101.675 ;
    END
  END w0_wd_in[49]
  PIN w0_wd_in[50]
    DIRECTION INPUT ;
    USE SIGNAL ;
    SHAPE ABUTMENT ;
    PORT
      LAYER metal3 ;
      RECT 122.910 103.705 123.120 103.775 ;
    END
  END w0_wd_in[50]
  PIN w0_wd_in[51]
    DIRECTION INPUT ;
    USE SIGNAL ;
    SHAPE ABUTMENT ;
    PORT
      LAYER metal3 ;
      RECT 122.910 105.805 123.120 105.875 ;
    END
  END w0_wd_in[51]
  PIN w0_wd_in[52]
    DIRECTION INPUT ;
    USE SIGNAL ;
    SHAPE ABUTMENT ;
    PORT
      LAYER metal3 ;
      RECT 122.910 107.905 123.120 107.975 ;
    END
  END w0_wd_in[52]
  PIN w0_wd_in[53]
    DIRECTION INPUT ;
    USE SIGNAL ;
    SHAPE ABUTMENT ;
    PORT
      LAYER metal3 ;
      RECT 122.910 110.005 123.120 110.075 ;
    END
  END w0_wd_in[53]
  PIN w0_wd_in[54]
    DIRECTION INPUT ;
    USE SIGNAL ;
    SHAPE ABUTMENT ;
    PORT
      LAYER metal3 ;
      RECT 122.910 112.105 123.120 112.175 ;
    END
  END w0_wd_in[54]
  PIN w0_wd_in[55]
    DIRECTION INPUT ;
    USE SIGNAL ;
    SHAPE ABUTMENT ;
    PORT
      LAYER metal3 ;
      RECT 122.910 114.205 123.120 114.275 ;
    END
  END w0_wd_in[55]
  PIN w0_wd_in[56]
    DIRECTION INPUT ;
    USE SIGNAL ;
    SHAPE ABUTMENT ;
    PORT
      LAYER metal3 ;
      RECT 122.910 116.305 123.120 116.375 ;
    END
  END w0_wd_in[56]
  PIN w0_wd_in[57]
    DIRECTION INPUT ;
    USE SIGNAL ;
    SHAPE ABUTMENT ;
    PORT
      LAYER metal3 ;
      RECT 122.910 118.405 123.120 118.475 ;
    END
  END w0_wd_in[57]
  PIN w0_wd_in[58]
    DIRECTION INPUT ;
    USE SIGNAL ;
    SHAPE ABUTMENT ;
    PORT
      LAYER metal3 ;
      RECT 122.910 120.505 123.120 120.575 ;
    END
  END w0_wd_in[58]
  PIN w0_wd_in[59]
    DIRECTION INPUT ;
    USE SIGNAL ;
    SHAPE ABUTMENT ;
    PORT
      LAYER metal3 ;
      RECT 122.910 122.605 123.120 122.675 ;
    END
  END w0_wd_in[59]
  PIN w0_wd_in[60]
    DIRECTION INPUT ;
    USE SIGNAL ;
    SHAPE ABUTMENT ;
    PORT
      LAYER metal3 ;
      RECT 122.910 124.705 123.120 124.775 ;
    END
  END w0_wd_in[60]
  PIN w0_wd_in[61]
    DIRECTION INPUT ;
    USE SIGNAL ;
    SHAPE ABUTMENT ;
    PORT
      LAYER metal3 ;
      RECT 122.910 126.805 123.120 126.875 ;
    END
  END w0_wd_in[61]
  PIN w0_wd_in[62]
    DIRECTION INPUT ;
    USE SIGNAL ;
    SHAPE ABUTMENT ;
    PORT
      LAYER metal3 ;
      RECT 122.910 128.905 123.120 128.975 ;
    END
  END w0_wd_in[62]
  PIN w0_wd_in[63]
    DIRECTION INPUT ;
    USE SIGNAL ;
    SHAPE ABUTMENT ;
    PORT
      LAYER metal3 ;
      RECT 122.910 131.005 123.120 131.075 ;
    END
  END w0_wd_in[63]
  PIN w0_wd_in[64]
    DIRECTION INPUT ;
    USE SIGNAL ;
    SHAPE ABUTMENT ;
    PORT
      LAYER metal3 ;
      RECT 122.910 133.105 123.120 133.175 ;
    END
  END w0_wd_in[64]
  PIN w0_wd_in[65]
    DIRECTION INPUT ;
    USE SIGNAL ;
    SHAPE ABUTMENT ;
    PORT
      LAYER metal3 ;
      RECT 122.910 135.205 123.120 135.275 ;
    END
  END w0_wd_in[65]
  PIN w0_wd_in[66]
    DIRECTION INPUT ;
    USE SIGNAL ;
    SHAPE ABUTMENT ;
    PORT
      LAYER metal3 ;
      RECT 122.910 137.305 123.120 137.375 ;
    END
  END w0_wd_in[66]
  PIN w0_wd_in[67]
    DIRECTION INPUT ;
    USE SIGNAL ;
    SHAPE ABUTMENT ;
    PORT
      LAYER metal3 ;
      RECT 122.910 139.405 123.120 139.475 ;
    END
  END w0_wd_in[67]
  PIN w0_wd_in[68]
    DIRECTION INPUT ;
    USE SIGNAL ;
    SHAPE ABUTMENT ;
    PORT
      LAYER metal3 ;
      RECT 122.910 141.505 123.120 141.575 ;
    END
  END w0_wd_in[68]
  PIN w0_wd_in[69]
    DIRECTION INPUT ;
    USE SIGNAL ;
    SHAPE ABUTMENT ;
    PORT
      LAYER metal3 ;
      RECT 122.910 143.605 123.120 143.675 ;
    END
  END w0_wd_in[69]
  PIN w0_wd_in[70]
    DIRECTION INPUT ;
    USE SIGNAL ;
    SHAPE ABUTMENT ;
    PORT
      LAYER metal3 ;
      RECT 122.910 145.705 123.120 145.775 ;
    END
  END w0_wd_in[70]
  PIN w0_wd_in[71]
    DIRECTION INPUT ;
    USE SIGNAL ;
    SHAPE ABUTMENT ;
    PORT
      LAYER metal3 ;
      RECT 122.910 147.805 123.120 147.875 ;
    END
  END w0_wd_in[71]
  PIN w0_wd_in[72]
    DIRECTION INPUT ;
    USE SIGNAL ;
    SHAPE ABUTMENT ;
    PORT
      LAYER metal3 ;
      RECT 122.910 149.905 123.120 149.975 ;
    END
  END w0_wd_in[72]
  PIN w0_wd_in[73]
    DIRECTION INPUT ;
    USE SIGNAL ;
    SHAPE ABUTMENT ;
    PORT
      LAYER metal3 ;
      RECT 122.910 152.005 123.120 152.075 ;
    END
  END w0_wd_in[73]
  PIN w0_wd_in[74]
    DIRECTION INPUT ;
    USE SIGNAL ;
    SHAPE ABUTMENT ;
    PORT
      LAYER metal3 ;
      RECT 122.910 154.105 123.120 154.175 ;
    END
  END w0_wd_in[74]
  PIN w0_wd_in[75]
    DIRECTION INPUT ;
    USE SIGNAL ;
    SHAPE ABUTMENT ;
    PORT
      LAYER metal3 ;
      RECT 122.910 156.205 123.120 156.275 ;
    END
  END w0_wd_in[75]
  PIN w0_wd_in[76]
    DIRECTION INPUT ;
    USE SIGNAL ;
    SHAPE ABUTMENT ;
    PORT
      LAYER metal3 ;
      RECT 122.910 158.305 123.120 158.375 ;
    END
  END w0_wd_in[76]
  PIN w0_wd_in[77]
    DIRECTION INPUT ;
    USE SIGNAL ;
    SHAPE ABUTMENT ;
    PORT
      LAYER metal3 ;
      RECT 122.910 160.405 123.120 160.475 ;
    END
  END w0_wd_in[77]
  PIN w0_wd_in[78]
    DIRECTION INPUT ;
    USE SIGNAL ;
    SHAPE ABUTMENT ;
    PORT
      LAYER metal3 ;
      RECT 122.910 162.505 123.120 162.575 ;
    END
  END w0_wd_in[78]
  PIN w0_wd_in[79]
    DIRECTION INPUT ;
    USE SIGNAL ;
    SHAPE ABUTMENT ;
    PORT
      LAYER metal3 ;
      RECT 122.910 164.605 123.120 164.675 ;
    END
  END w0_wd_in[79]
  PIN w0_wd_in[80]
    DIRECTION INPUT ;
    USE SIGNAL ;
    SHAPE ABUTMENT ;
    PORT
      LAYER metal3 ;
      RECT 122.910 166.705 123.120 166.775 ;
    END
  END w0_wd_in[80]
  PIN w0_wd_in[81]
    DIRECTION INPUT ;
    USE SIGNAL ;
    SHAPE ABUTMENT ;
    PORT
      LAYER metal3 ;
      RECT 122.910 168.805 123.120 168.875 ;
    END
  END w0_wd_in[81]
  PIN w0_wd_in[82]
    DIRECTION INPUT ;
    USE SIGNAL ;
    SHAPE ABUTMENT ;
    PORT
      LAYER metal3 ;
      RECT 122.910 170.905 123.120 170.975 ;
    END
  END w0_wd_in[82]
  PIN w0_wd_in[83]
    DIRECTION INPUT ;
    USE SIGNAL ;
    SHAPE ABUTMENT ;
    PORT
      LAYER metal3 ;
      RECT 122.910 173.005 123.120 173.075 ;
    END
  END w0_wd_in[83]
  PIN w0_wd_in[84]
    DIRECTION INPUT ;
    USE SIGNAL ;
    SHAPE ABUTMENT ;
    PORT
      LAYER metal3 ;
      RECT 122.910 175.105 123.120 175.175 ;
    END
  END w0_wd_in[84]
  PIN w0_wd_in[85]
    DIRECTION INPUT ;
    USE SIGNAL ;
    SHAPE ABUTMENT ;
    PORT
      LAYER metal3 ;
      RECT 122.910 177.205 123.120 177.275 ;
    END
  END w0_wd_in[85]
  PIN w0_wd_in[86]
    DIRECTION INPUT ;
    USE SIGNAL ;
    SHAPE ABUTMENT ;
    PORT
      LAYER metal3 ;
      RECT 122.910 179.305 123.120 179.375 ;
    END
  END w0_wd_in[86]
  PIN w0_wd_in[87]
    DIRECTION INPUT ;
    USE SIGNAL ;
    SHAPE ABUTMENT ;
    PORT
      LAYER metal3 ;
      RECT 122.910 181.405 123.120 181.475 ;
    END
  END w0_wd_in[87]
  PIN w0_wd_in[88]
    DIRECTION INPUT ;
    USE SIGNAL ;
    SHAPE ABUTMENT ;
    PORT
      LAYER metal3 ;
      RECT 122.910 183.505 123.120 183.575 ;
    END
  END w0_wd_in[88]
  PIN w0_wd_in[89]
    DIRECTION INPUT ;
    USE SIGNAL ;
    SHAPE ABUTMENT ;
    PORT
      LAYER metal3 ;
      RECT 122.910 185.605 123.120 185.675 ;
    END
  END w0_wd_in[89]
  PIN w0_wd_in[90]
    DIRECTION INPUT ;
    USE SIGNAL ;
    SHAPE ABUTMENT ;
    PORT
      LAYER metal3 ;
      RECT 122.910 187.705 123.120 187.775 ;
    END
  END w0_wd_in[90]
  PIN w0_wd_in[91]
    DIRECTION INPUT ;
    USE SIGNAL ;
    SHAPE ABUTMENT ;
    PORT
      LAYER metal3 ;
      RECT 122.910 189.805 123.120 189.875 ;
    END
  END w0_wd_in[91]
  PIN w0_wd_in[92]
    DIRECTION INPUT ;
    USE SIGNAL ;
    SHAPE ABUTMENT ;
    PORT
      LAYER metal3 ;
      RECT 122.910 191.905 123.120 191.975 ;
    END
  END w0_wd_in[92]
  PIN w0_wd_in[93]
    DIRECTION INPUT ;
    USE SIGNAL ;
    SHAPE ABUTMENT ;
    PORT
      LAYER metal3 ;
      RECT 122.910 194.005 123.120 194.075 ;
    END
  END w0_wd_in[93]
  PIN w0_wd_in[94]
    DIRECTION INPUT ;
    USE SIGNAL ;
    SHAPE ABUTMENT ;
    PORT
      LAYER metal3 ;
      RECT 122.910 196.105 123.120 196.175 ;
    END
  END w0_wd_in[94]
  PIN w0_wd_in[95]
    DIRECTION INPUT ;
    USE SIGNAL ;
    SHAPE ABUTMENT ;
    PORT
      LAYER metal3 ;
      RECT 122.910 198.205 123.120 198.275 ;
    END
  END w0_wd_in[95]
  PIN w0_wd_in[96]
    DIRECTION INPUT ;
    USE SIGNAL ;
    SHAPE ABUTMENT ;
    PORT
      LAYER metal3 ;
      RECT 122.910 200.305 123.120 200.375 ;
    END
  END w0_wd_in[96]
  PIN w0_wd_in[97]
    DIRECTION OUTPUT ;
    USE SIGNAL ;
    SHAPE ABUTMENT ;
    PORT
      LAYER metal2 ;
      RECT 1.105 0.000 1.175 0.210 ;
    END
  END w0_wd_in[97]
  PIN w0_wd_in[98]
    DIRECTION OUTPUT ;
    USE SIGNAL ;
    SHAPE ABUTMENT ;
    PORT
      LAYER metal2 ;
      RECT 1.675 0.000 1.745 0.210 ;
    END
  END w0_wd_in[98]
  PIN w0_wd_in[99]
    DIRECTION OUTPUT ;
    USE SIGNAL ;
    SHAPE ABUTMENT ;
    PORT
      LAYER metal2 ;
      RECT 2.245 0.000 2.315 0.210 ;
    END
  END w0_wd_in[99]
  PIN w0_wd_in[100]
    DIRECTION OUTPUT ;
    USE SIGNAL ;
    SHAPE ABUTMENT ;
    PORT
      LAYER metal2 ;
      RECT 2.815 0.000 2.885 0.210 ;
    END
  END w0_wd_in[100]
  PIN w0_wd_in[101]
    DIRECTION OUTPUT ;
    USE SIGNAL ;
    SHAPE ABUTMENT ;
    PORT
      LAYER metal2 ;
      RECT 3.385 0.000 3.455 0.210 ;
    END
  END w0_wd_in[101]
  PIN w0_wd_in[102]
    DIRECTION OUTPUT ;
    USE SIGNAL ;
    SHAPE ABUTMENT ;
    PORT
      LAYER metal2 ;
      RECT 3.955 0.000 4.025 0.210 ;
    END
  END w0_wd_in[102]
  PIN w0_wd_in[103]
    DIRECTION OUTPUT ;
    USE SIGNAL ;
    SHAPE ABUTMENT ;
    PORT
      LAYER metal2 ;
      RECT 4.525 0.000 4.595 0.210 ;
    END
  END w0_wd_in[103]
  PIN w0_wd_in[104]
    DIRECTION OUTPUT ;
    USE SIGNAL ;
    SHAPE ABUTMENT ;
    PORT
      LAYER metal2 ;
      RECT 5.095 0.000 5.165 0.210 ;
    END
  END w0_wd_in[104]
  PIN w0_wd_in[105]
    DIRECTION OUTPUT ;
    USE SIGNAL ;
    SHAPE ABUTMENT ;
    PORT
      LAYER metal2 ;
      RECT 5.665 0.000 5.735 0.210 ;
    END
  END w0_wd_in[105]
  PIN w0_wd_in[106]
    DIRECTION OUTPUT ;
    USE SIGNAL ;
    SHAPE ABUTMENT ;
    PORT
      LAYER metal2 ;
      RECT 6.235 0.000 6.305 0.210 ;
    END
  END w0_wd_in[106]
  PIN w0_wd_in[107]
    DIRECTION OUTPUT ;
    USE SIGNAL ;
    SHAPE ABUTMENT ;
    PORT
      LAYER metal2 ;
      RECT 6.805 0.000 6.875 0.210 ;
    END
  END w0_wd_in[107]
  PIN w0_wd_in[108]
    DIRECTION OUTPUT ;
    USE SIGNAL ;
    SHAPE ABUTMENT ;
    PORT
      LAYER metal2 ;
      RECT 7.375 0.000 7.445 0.210 ;
    END
  END w0_wd_in[108]
  PIN w0_wd_in[109]
    DIRECTION OUTPUT ;
    USE SIGNAL ;
    SHAPE ABUTMENT ;
    PORT
      LAYER metal2 ;
      RECT 7.945 0.000 8.015 0.210 ;
    END
  END w0_wd_in[109]
  PIN w0_wd_in[110]
    DIRECTION OUTPUT ;
    USE SIGNAL ;
    SHAPE ABUTMENT ;
    PORT
      LAYER metal2 ;
      RECT 8.515 0.000 8.585 0.210 ;
    END
  END w0_wd_in[110]
  PIN w0_wd_in[111]
    DIRECTION OUTPUT ;
    USE SIGNAL ;
    SHAPE ABUTMENT ;
    PORT
      LAYER metal2 ;
      RECT 9.085 0.000 9.155 0.210 ;
    END
  END w0_wd_in[111]
  PIN w0_wd_in[112]
    DIRECTION OUTPUT ;
    USE SIGNAL ;
    SHAPE ABUTMENT ;
    PORT
      LAYER metal2 ;
      RECT 9.655 0.000 9.725 0.210 ;
    END
  END w0_wd_in[112]
  PIN w0_wd_in[113]
    DIRECTION OUTPUT ;
    USE SIGNAL ;
    SHAPE ABUTMENT ;
    PORT
      LAYER metal2 ;
      RECT 10.225 0.000 10.295 0.210 ;
    END
  END w0_wd_in[113]
  PIN w0_wd_in[114]
    DIRECTION OUTPUT ;
    USE SIGNAL ;
    SHAPE ABUTMENT ;
    PORT
      LAYER metal2 ;
      RECT 10.795 0.000 10.865 0.210 ;
    END
  END w0_wd_in[114]
  PIN w0_wd_in[115]
    DIRECTION OUTPUT ;
    USE SIGNAL ;
    SHAPE ABUTMENT ;
    PORT
      LAYER metal2 ;
      RECT 11.365 0.000 11.435 0.210 ;
    END
  END w0_wd_in[115]
  PIN w0_wd_in[116]
    DIRECTION OUTPUT ;
    USE SIGNAL ;
    SHAPE ABUTMENT ;
    PORT
      LAYER metal2 ;
      RECT 11.935 0.000 12.005 0.210 ;
    END
  END w0_wd_in[116]
  PIN w0_wd_in[117]
    DIRECTION OUTPUT ;
    USE SIGNAL ;
    SHAPE ABUTMENT ;
    PORT
      LAYER metal2 ;
      RECT 12.505 0.000 12.575 0.210 ;
    END
  END w0_wd_in[117]
  PIN w0_wd_in[118]
    DIRECTION OUTPUT ;
    USE SIGNAL ;
    SHAPE ABUTMENT ;
    PORT
      LAYER metal2 ;
      RECT 13.075 0.000 13.145 0.210 ;
    END
  END w0_wd_in[118]
  PIN w0_wd_in[119]
    DIRECTION OUTPUT ;
    USE SIGNAL ;
    SHAPE ABUTMENT ;
    PORT
      LAYER metal2 ;
      RECT 13.645 0.000 13.715 0.210 ;
    END
  END w0_wd_in[119]
  PIN w0_wd_in[120]
    DIRECTION OUTPUT ;
    USE SIGNAL ;
    SHAPE ABUTMENT ;
    PORT
      LAYER metal2 ;
      RECT 14.215 0.000 14.285 0.210 ;
    END
  END w0_wd_in[120]
  PIN w0_wd_in[121]
    DIRECTION OUTPUT ;
    USE SIGNAL ;
    SHAPE ABUTMENT ;
    PORT
      LAYER metal2 ;
      RECT 14.785 0.000 14.855 0.210 ;
    END
  END w0_wd_in[121]
  PIN w0_wd_in[122]
    DIRECTION OUTPUT ;
    USE SIGNAL ;
    SHAPE ABUTMENT ;
    PORT
      LAYER metal2 ;
      RECT 15.355 0.000 15.425 0.210 ;
    END
  END w0_wd_in[122]
  PIN w0_wd_in[123]
    DIRECTION OUTPUT ;
    USE SIGNAL ;
    SHAPE ABUTMENT ;
    PORT
      LAYER metal2 ;
      RECT 15.925 0.000 15.995 0.210 ;
    END
  END w0_wd_in[123]
  PIN w0_wd_in[124]
    DIRECTION OUTPUT ;
    USE SIGNAL ;
    SHAPE ABUTMENT ;
    PORT
      LAYER metal2 ;
      RECT 16.495 0.000 16.565 0.210 ;
    END
  END w0_wd_in[124]
  PIN w0_wd_in[125]
    DIRECTION OUTPUT ;
    USE SIGNAL ;
    SHAPE ABUTMENT ;
    PORT
      LAYER metal2 ;
      RECT 17.065 0.000 17.135 0.210 ;
    END
  END w0_wd_in[125]
  PIN w0_wd_in[126]
    DIRECTION OUTPUT ;
    USE SIGNAL ;
    SHAPE ABUTMENT ;
    PORT
      LAYER metal2 ;
      RECT 17.635 0.000 17.705 0.210 ;
    END
  END w0_wd_in[126]
  PIN w0_wd_in[127]
    DIRECTION OUTPUT ;
    USE SIGNAL ;
    SHAPE ABUTMENT ;
    PORT
      LAYER metal2 ;
      RECT 18.205 0.000 18.275 0.210 ;
    END
  END w0_wd_in[127]
  PIN w0_wd_in[128]
    DIRECTION OUTPUT ;
    USE SIGNAL ;
    SHAPE ABUTMENT ;
    PORT
      LAYER metal2 ;
      RECT 18.775 0.000 18.845 0.210 ;
    END
  END w0_wd_in[128]
  PIN w0_wd_in[129]
    DIRECTION OUTPUT ;
    USE SIGNAL ;
    SHAPE ABUTMENT ;
    PORT
      LAYER metal2 ;
      RECT 19.345 0.000 19.415 0.210 ;
    END
  END w0_wd_in[129]
  PIN w0_wd_in[130]
    DIRECTION OUTPUT ;
    USE SIGNAL ;
    SHAPE ABUTMENT ;
    PORT
      LAYER metal2 ;
      RECT 19.915 0.000 19.985 0.210 ;
    END
  END w0_wd_in[130]
  PIN w0_wd_in[131]
    DIRECTION OUTPUT ;
    USE SIGNAL ;
    SHAPE ABUTMENT ;
    PORT
      LAYER metal2 ;
      RECT 20.485 0.000 20.555 0.210 ;
    END
  END w0_wd_in[131]
  PIN w0_wd_in[132]
    DIRECTION OUTPUT ;
    USE SIGNAL ;
    SHAPE ABUTMENT ;
    PORT
      LAYER metal2 ;
      RECT 21.055 0.000 21.125 0.210 ;
    END
  END w0_wd_in[132]
  PIN w0_wd_in[133]
    DIRECTION OUTPUT ;
    USE SIGNAL ;
    SHAPE ABUTMENT ;
    PORT
      LAYER metal2 ;
      RECT 21.625 0.000 21.695 0.210 ;
    END
  END w0_wd_in[133]
  PIN w0_wd_in[134]
    DIRECTION OUTPUT ;
    USE SIGNAL ;
    SHAPE ABUTMENT ;
    PORT
      LAYER metal2 ;
      RECT 22.195 0.000 22.265 0.210 ;
    END
  END w0_wd_in[134]
  PIN w0_wd_in[135]
    DIRECTION OUTPUT ;
    USE SIGNAL ;
    SHAPE ABUTMENT ;
    PORT
      LAYER metal2 ;
      RECT 22.765 0.000 22.835 0.210 ;
    END
  END w0_wd_in[135]
  PIN w0_wd_in[136]
    DIRECTION OUTPUT ;
    USE SIGNAL ;
    SHAPE ABUTMENT ;
    PORT
      LAYER metal2 ;
      RECT 23.335 0.000 23.405 0.210 ;
    END
  END w0_wd_in[136]
  PIN w0_wd_in[137]
    DIRECTION OUTPUT ;
    USE SIGNAL ;
    SHAPE ABUTMENT ;
    PORT
      LAYER metal2 ;
      RECT 23.905 0.000 23.975 0.210 ;
    END
  END w0_wd_in[137]
  PIN w0_wd_in[138]
    DIRECTION OUTPUT ;
    USE SIGNAL ;
    SHAPE ABUTMENT ;
    PORT
      LAYER metal2 ;
      RECT 24.475 0.000 24.545 0.210 ;
    END
  END w0_wd_in[138]
  PIN w0_wd_in[139]
    DIRECTION OUTPUT ;
    USE SIGNAL ;
    SHAPE ABUTMENT ;
    PORT
      LAYER metal2 ;
      RECT 25.045 0.000 25.115 0.210 ;
    END
  END w0_wd_in[139]
  PIN w0_wd_in[140]
    DIRECTION OUTPUT ;
    USE SIGNAL ;
    SHAPE ABUTMENT ;
    PORT
      LAYER metal2 ;
      RECT 25.615 0.000 25.685 0.210 ;
    END
  END w0_wd_in[140]
  PIN w0_wd_in[141]
    DIRECTION OUTPUT ;
    USE SIGNAL ;
    SHAPE ABUTMENT ;
    PORT
      LAYER metal2 ;
      RECT 26.185 0.000 26.255 0.210 ;
    END
  END w0_wd_in[141]
  PIN w0_wd_in[142]
    DIRECTION OUTPUT ;
    USE SIGNAL ;
    SHAPE ABUTMENT ;
    PORT
      LAYER metal2 ;
      RECT 26.755 0.000 26.825 0.210 ;
    END
  END w0_wd_in[142]
  PIN w0_wd_in[143]
    DIRECTION OUTPUT ;
    USE SIGNAL ;
    SHAPE ABUTMENT ;
    PORT
      LAYER metal2 ;
      RECT 27.325 0.000 27.395 0.210 ;
    END
  END w0_wd_in[143]
  PIN w0_wd_in[144]
    DIRECTION OUTPUT ;
    USE SIGNAL ;
    SHAPE ABUTMENT ;
    PORT
      LAYER metal2 ;
      RECT 27.895 0.000 27.965 0.210 ;
    END
  END w0_wd_in[144]
  PIN w0_wd_in[145]
    DIRECTION OUTPUT ;
    USE SIGNAL ;
    SHAPE ABUTMENT ;
    PORT
      LAYER metal2 ;
      RECT 28.465 0.000 28.535 0.210 ;
    END
  END w0_wd_in[145]
  PIN w0_wd_in[146]
    DIRECTION OUTPUT ;
    USE SIGNAL ;
    SHAPE ABUTMENT ;
    PORT
      LAYER metal2 ;
      RECT 29.035 0.000 29.105 0.210 ;
    END
  END w0_wd_in[146]
  PIN w0_wd_in[147]
    DIRECTION OUTPUT ;
    USE SIGNAL ;
    SHAPE ABUTMENT ;
    PORT
      LAYER metal2 ;
      RECT 29.605 0.000 29.675 0.210 ;
    END
  END w0_wd_in[147]
  PIN w0_wd_in[148]
    DIRECTION OUTPUT ;
    USE SIGNAL ;
    SHAPE ABUTMENT ;
    PORT
      LAYER metal2 ;
      RECT 30.175 0.000 30.245 0.210 ;
    END
  END w0_wd_in[148]
  PIN w0_wd_in[149]
    DIRECTION OUTPUT ;
    USE SIGNAL ;
    SHAPE ABUTMENT ;
    PORT
      LAYER metal2 ;
      RECT 30.745 0.000 30.815 0.210 ;
    END
  END w0_wd_in[149]
  PIN w0_wd_in[150]
    DIRECTION OUTPUT ;
    USE SIGNAL ;
    SHAPE ABUTMENT ;
    PORT
      LAYER metal2 ;
      RECT 31.315 0.000 31.385 0.210 ;
    END
  END w0_wd_in[150]
  PIN w0_wd_in[151]
    DIRECTION OUTPUT ;
    USE SIGNAL ;
    SHAPE ABUTMENT ;
    PORT
      LAYER metal2 ;
      RECT 31.885 0.000 31.955 0.210 ;
    END
  END w0_wd_in[151]
  PIN w0_wd_in[152]
    DIRECTION OUTPUT ;
    USE SIGNAL ;
    SHAPE ABUTMENT ;
    PORT
      LAYER metal2 ;
      RECT 32.455 0.000 32.525 0.210 ;
    END
  END w0_wd_in[152]
  PIN w0_wd_in[153]
    DIRECTION OUTPUT ;
    USE SIGNAL ;
    SHAPE ABUTMENT ;
    PORT
      LAYER metal2 ;
      RECT 33.025 0.000 33.095 0.210 ;
    END
  END w0_wd_in[153]
  PIN w0_wd_in[154]
    DIRECTION OUTPUT ;
    USE SIGNAL ;
    SHAPE ABUTMENT ;
    PORT
      LAYER metal2 ;
      RECT 33.595 0.000 33.665 0.210 ;
    END
  END w0_wd_in[154]
  PIN w0_wd_in[155]
    DIRECTION OUTPUT ;
    USE SIGNAL ;
    SHAPE ABUTMENT ;
    PORT
      LAYER metal2 ;
      RECT 34.165 0.000 34.235 0.210 ;
    END
  END w0_wd_in[155]
  PIN w0_wd_in[156]
    DIRECTION OUTPUT ;
    USE SIGNAL ;
    SHAPE ABUTMENT ;
    PORT
      LAYER metal2 ;
      RECT 34.735 0.000 34.805 0.210 ;
    END
  END w0_wd_in[156]
  PIN w0_wd_in[157]
    DIRECTION OUTPUT ;
    USE SIGNAL ;
    SHAPE ABUTMENT ;
    PORT
      LAYER metal2 ;
      RECT 35.305 0.000 35.375 0.210 ;
    END
  END w0_wd_in[157]
  PIN w0_wd_in[158]
    DIRECTION OUTPUT ;
    USE SIGNAL ;
    SHAPE ABUTMENT ;
    PORT
      LAYER metal2 ;
      RECT 35.875 0.000 35.945 0.210 ;
    END
  END w0_wd_in[158]
  PIN w0_wd_in[159]
    DIRECTION OUTPUT ;
    USE SIGNAL ;
    SHAPE ABUTMENT ;
    PORT
      LAYER metal2 ;
      RECT 36.445 0.000 36.515 0.210 ;
    END
  END w0_wd_in[159]
  PIN w0_wd_in[160]
    DIRECTION OUTPUT ;
    USE SIGNAL ;
    SHAPE ABUTMENT ;
    PORT
      LAYER metal2 ;
      RECT 37.015 0.000 37.085 0.210 ;
    END
  END w0_wd_in[160]
  PIN w0_wd_in[161]
    DIRECTION OUTPUT ;
    USE SIGNAL ;
    SHAPE ABUTMENT ;
    PORT
      LAYER metal2 ;
      RECT 37.585 0.000 37.655 0.210 ;
    END
  END w0_wd_in[161]
  PIN w0_wd_in[162]
    DIRECTION OUTPUT ;
    USE SIGNAL ;
    SHAPE ABUTMENT ;
    PORT
      LAYER metal2 ;
      RECT 38.155 0.000 38.225 0.210 ;
    END
  END w0_wd_in[162]
  PIN w0_wd_in[163]
    DIRECTION OUTPUT ;
    USE SIGNAL ;
    SHAPE ABUTMENT ;
    PORT
      LAYER metal2 ;
      RECT 38.725 0.000 38.795 0.210 ;
    END
  END w0_wd_in[163]
  PIN w0_wd_in[164]
    DIRECTION OUTPUT ;
    USE SIGNAL ;
    SHAPE ABUTMENT ;
    PORT
      LAYER metal2 ;
      RECT 39.295 0.000 39.365 0.210 ;
    END
  END w0_wd_in[164]
  PIN w0_wd_in[165]
    DIRECTION OUTPUT ;
    USE SIGNAL ;
    SHAPE ABUTMENT ;
    PORT
      LAYER metal2 ;
      RECT 39.865 0.000 39.935 0.210 ;
    END
  END w0_wd_in[165]
  PIN w0_wd_in[166]
    DIRECTION OUTPUT ;
    USE SIGNAL ;
    SHAPE ABUTMENT ;
    PORT
      LAYER metal2 ;
      RECT 40.435 0.000 40.505 0.210 ;
    END
  END w0_wd_in[166]
  PIN w0_wd_in[167]
    DIRECTION OUTPUT ;
    USE SIGNAL ;
    SHAPE ABUTMENT ;
    PORT
      LAYER metal2 ;
      RECT 41.005 0.000 41.075 0.210 ;
    END
  END w0_wd_in[167]
  PIN w0_wd_in[168]
    DIRECTION OUTPUT ;
    USE SIGNAL ;
    SHAPE ABUTMENT ;
    PORT
      LAYER metal2 ;
      RECT 41.575 0.000 41.645 0.210 ;
    END
  END w0_wd_in[168]
  PIN w0_wd_in[169]
    DIRECTION OUTPUT ;
    USE SIGNAL ;
    SHAPE ABUTMENT ;
    PORT
      LAYER metal2 ;
      RECT 42.145 0.000 42.215 0.210 ;
    END
  END w0_wd_in[169]
  PIN w0_wd_in[170]
    DIRECTION OUTPUT ;
    USE SIGNAL ;
    SHAPE ABUTMENT ;
    PORT
      LAYER metal2 ;
      RECT 42.715 0.000 42.785 0.210 ;
    END
  END w0_wd_in[170]
  PIN w0_wd_in[171]
    DIRECTION OUTPUT ;
    USE SIGNAL ;
    SHAPE ABUTMENT ;
    PORT
      LAYER metal2 ;
      RECT 43.285 0.000 43.355 0.210 ;
    END
  END w0_wd_in[171]
  PIN w0_wd_in[172]
    DIRECTION OUTPUT ;
    USE SIGNAL ;
    SHAPE ABUTMENT ;
    PORT
      LAYER metal2 ;
      RECT 43.855 0.000 43.925 0.210 ;
    END
  END w0_wd_in[172]
  PIN w0_wd_in[173]
    DIRECTION OUTPUT ;
    USE SIGNAL ;
    SHAPE ABUTMENT ;
    PORT
      LAYER metal2 ;
      RECT 44.425 0.000 44.495 0.210 ;
    END
  END w0_wd_in[173]
  PIN w0_wd_in[174]
    DIRECTION OUTPUT ;
    USE SIGNAL ;
    SHAPE ABUTMENT ;
    PORT
      LAYER metal2 ;
      RECT 44.995 0.000 45.065 0.210 ;
    END
  END w0_wd_in[174]
  PIN w0_wd_in[175]
    DIRECTION OUTPUT ;
    USE SIGNAL ;
    SHAPE ABUTMENT ;
    PORT
      LAYER metal2 ;
      RECT 45.565 0.000 45.635 0.210 ;
    END
  END w0_wd_in[175]
  PIN w0_wd_in[176]
    DIRECTION OUTPUT ;
    USE SIGNAL ;
    SHAPE ABUTMENT ;
    PORT
      LAYER metal2 ;
      RECT 46.135 0.000 46.205 0.210 ;
    END
  END w0_wd_in[176]
  PIN w0_wd_in[177]
    DIRECTION OUTPUT ;
    USE SIGNAL ;
    SHAPE ABUTMENT ;
    PORT
      LAYER metal2 ;
      RECT 46.705 0.000 46.775 0.210 ;
    END
  END w0_wd_in[177]
  PIN w0_wd_in[178]
    DIRECTION OUTPUT ;
    USE SIGNAL ;
    SHAPE ABUTMENT ;
    PORT
      LAYER metal2 ;
      RECT 47.275 0.000 47.345 0.210 ;
    END
  END w0_wd_in[178]
  PIN w0_wd_in[179]
    DIRECTION OUTPUT ;
    USE SIGNAL ;
    SHAPE ABUTMENT ;
    PORT
      LAYER metal2 ;
      RECT 47.845 0.000 47.915 0.210 ;
    END
  END w0_wd_in[179]
  PIN w0_wd_in[180]
    DIRECTION OUTPUT ;
    USE SIGNAL ;
    SHAPE ABUTMENT ;
    PORT
      LAYER metal2 ;
      RECT 48.415 0.000 48.485 0.210 ;
    END
  END w0_wd_in[180]
  PIN w0_wd_in[181]
    DIRECTION OUTPUT ;
    USE SIGNAL ;
    SHAPE ABUTMENT ;
    PORT
      LAYER metal2 ;
      RECT 48.985 0.000 49.055 0.210 ;
    END
  END w0_wd_in[181]
  PIN w0_wd_in[182]
    DIRECTION OUTPUT ;
    USE SIGNAL ;
    SHAPE ABUTMENT ;
    PORT
      LAYER metal2 ;
      RECT 49.555 0.000 49.625 0.210 ;
    END
  END w0_wd_in[182]
  PIN w0_wd_in[183]
    DIRECTION OUTPUT ;
    USE SIGNAL ;
    SHAPE ABUTMENT ;
    PORT
      LAYER metal2 ;
      RECT 50.125 0.000 50.195 0.210 ;
    END
  END w0_wd_in[183]
  PIN w0_wd_in[184]
    DIRECTION OUTPUT ;
    USE SIGNAL ;
    SHAPE ABUTMENT ;
    PORT
      LAYER metal2 ;
      RECT 50.695 0.000 50.765 0.210 ;
    END
  END w0_wd_in[184]
  PIN w0_wd_in[185]
    DIRECTION OUTPUT ;
    USE SIGNAL ;
    SHAPE ABUTMENT ;
    PORT
      LAYER metal2 ;
      RECT 51.265 0.000 51.335 0.210 ;
    END
  END w0_wd_in[185]
  PIN w0_wd_in[186]
    DIRECTION OUTPUT ;
    USE SIGNAL ;
    SHAPE ABUTMENT ;
    PORT
      LAYER metal2 ;
      RECT 51.835 0.000 51.905 0.210 ;
    END
  END w0_wd_in[186]
  PIN w0_wd_in[187]
    DIRECTION OUTPUT ;
    USE SIGNAL ;
    SHAPE ABUTMENT ;
    PORT
      LAYER metal2 ;
      RECT 52.405 0.000 52.475 0.210 ;
    END
  END w0_wd_in[187]
  PIN w0_wd_in[188]
    DIRECTION OUTPUT ;
    USE SIGNAL ;
    SHAPE ABUTMENT ;
    PORT
      LAYER metal2 ;
      RECT 52.975 0.000 53.045 0.210 ;
    END
  END w0_wd_in[188]
  PIN w0_wd_in[189]
    DIRECTION OUTPUT ;
    USE SIGNAL ;
    SHAPE ABUTMENT ;
    PORT
      LAYER metal2 ;
      RECT 53.545 0.000 53.615 0.210 ;
    END
  END w0_wd_in[189]
  PIN w0_wd_in[190]
    DIRECTION OUTPUT ;
    USE SIGNAL ;
    SHAPE ABUTMENT ;
    PORT
      LAYER metal2 ;
      RECT 54.115 0.000 54.185 0.210 ;
    END
  END w0_wd_in[190]
  PIN w0_wd_in[191]
    DIRECTION OUTPUT ;
    USE SIGNAL ;
    SHAPE ABUTMENT ;
    PORT
      LAYER metal2 ;
      RECT 54.685 0.000 54.755 0.210 ;
    END
  END w0_wd_in[191]
  PIN w0_wd_in[192]
    DIRECTION OUTPUT ;
    USE SIGNAL ;
    SHAPE ABUTMENT ;
    PORT
      LAYER metal2 ;
      RECT 55.255 0.000 55.325 0.210 ;
    END
  END w0_wd_in[192]
  PIN r0_rd_out[0]
    DIRECTION OUTPUT ;
    USE SIGNAL ;
    SHAPE ABUTMENT ;
    PORT
      LAYER metal2 ;
      RECT 55.825 0.000 55.895 0.210 ;
    END
  END r0_rd_out[0]
  PIN r0_rd_out[1]
    DIRECTION OUTPUT ;
    USE SIGNAL ;
    SHAPE ABUTMENT ;
    PORT
      LAYER metal2 ;
      RECT 56.395 0.000 56.465 0.210 ;
    END
  END r0_rd_out[1]
  PIN r0_rd_out[2]
    DIRECTION OUTPUT ;
    USE SIGNAL ;
    SHAPE ABUTMENT ;
    PORT
      LAYER metal2 ;
      RECT 56.965 0.000 57.035 0.210 ;
    END
  END r0_rd_out[2]
  PIN r0_rd_out[3]
    DIRECTION OUTPUT ;
    USE SIGNAL ;
    SHAPE ABUTMENT ;
    PORT
      LAYER metal2 ;
      RECT 57.535 0.000 57.605 0.210 ;
    END
  END r0_rd_out[3]
  PIN r0_rd_out[4]
    DIRECTION OUTPUT ;
    USE SIGNAL ;
    SHAPE ABUTMENT ;
    PORT
      LAYER metal2 ;
      RECT 58.105 0.000 58.175 0.210 ;
    END
  END r0_rd_out[4]
  PIN r0_rd_out[5]
    DIRECTION OUTPUT ;
    USE SIGNAL ;
    SHAPE ABUTMENT ;
    PORT
      LAYER metal2 ;
      RECT 58.675 0.000 58.745 0.210 ;
    END
  END r0_rd_out[5]
  PIN r0_rd_out[6]
    DIRECTION OUTPUT ;
    USE SIGNAL ;
    SHAPE ABUTMENT ;
    PORT
      LAYER metal2 ;
      RECT 59.245 0.000 59.315 0.210 ;
    END
  END r0_rd_out[6]
  PIN r0_rd_out[7]
    DIRECTION OUTPUT ;
    USE SIGNAL ;
    SHAPE ABUTMENT ;
    PORT
      LAYER metal2 ;
      RECT 59.815 0.000 59.885 0.210 ;
    END
  END r0_rd_out[7]
  PIN r0_rd_out[8]
    DIRECTION OUTPUT ;
    USE SIGNAL ;
    SHAPE ABUTMENT ;
    PORT
      LAYER metal2 ;
      RECT 60.385 0.000 60.455 0.210 ;
    END
  END r0_rd_out[8]
  PIN r0_rd_out[9]
    DIRECTION OUTPUT ;
    USE SIGNAL ;
    SHAPE ABUTMENT ;
    PORT
      LAYER metal2 ;
      RECT 60.955 0.000 61.025 0.210 ;
    END
  END r0_rd_out[9]
  PIN r0_rd_out[10]
    DIRECTION OUTPUT ;
    USE SIGNAL ;
    SHAPE ABUTMENT ;
    PORT
      LAYER metal2 ;
      RECT 61.525 0.000 61.595 0.210 ;
    END
  END r0_rd_out[10]
  PIN r0_rd_out[11]
    DIRECTION OUTPUT ;
    USE SIGNAL ;
    SHAPE ABUTMENT ;
    PORT
      LAYER metal2 ;
      RECT 62.095 0.000 62.165 0.210 ;
    END
  END r0_rd_out[11]
  PIN r0_rd_out[12]
    DIRECTION OUTPUT ;
    USE SIGNAL ;
    SHAPE ABUTMENT ;
    PORT
      LAYER metal2 ;
      RECT 62.665 0.000 62.735 0.210 ;
    END
  END r0_rd_out[12]
  PIN r0_rd_out[13]
    DIRECTION OUTPUT ;
    USE SIGNAL ;
    SHAPE ABUTMENT ;
    PORT
      LAYER metal2 ;
      RECT 63.235 0.000 63.305 0.210 ;
    END
  END r0_rd_out[13]
  PIN r0_rd_out[14]
    DIRECTION OUTPUT ;
    USE SIGNAL ;
    SHAPE ABUTMENT ;
    PORT
      LAYER metal2 ;
      RECT 63.805 0.000 63.875 0.210 ;
    END
  END r0_rd_out[14]
  PIN r0_rd_out[15]
    DIRECTION OUTPUT ;
    USE SIGNAL ;
    SHAPE ABUTMENT ;
    PORT
      LAYER metal2 ;
      RECT 64.375 0.000 64.445 0.210 ;
    END
  END r0_rd_out[15]
  PIN r0_rd_out[16]
    DIRECTION OUTPUT ;
    USE SIGNAL ;
    SHAPE ABUTMENT ;
    PORT
      LAYER metal2 ;
      RECT 64.945 0.000 65.015 0.210 ;
    END
  END r0_rd_out[16]
  PIN r0_rd_out[17]
    DIRECTION OUTPUT ;
    USE SIGNAL ;
    SHAPE ABUTMENT ;
    PORT
      LAYER metal2 ;
      RECT 65.515 0.000 65.585 0.210 ;
    END
  END r0_rd_out[17]
  PIN r0_rd_out[18]
    DIRECTION OUTPUT ;
    USE SIGNAL ;
    SHAPE ABUTMENT ;
    PORT
      LAYER metal2 ;
      RECT 66.085 0.000 66.155 0.210 ;
    END
  END r0_rd_out[18]
  PIN r0_rd_out[19]
    DIRECTION OUTPUT ;
    USE SIGNAL ;
    SHAPE ABUTMENT ;
    PORT
      LAYER metal2 ;
      RECT 66.655 0.000 66.725 0.210 ;
    END
  END r0_rd_out[19]
  PIN r0_rd_out[20]
    DIRECTION OUTPUT ;
    USE SIGNAL ;
    SHAPE ABUTMENT ;
    PORT
      LAYER metal2 ;
      RECT 67.225 0.000 67.295 0.210 ;
    END
  END r0_rd_out[20]
  PIN r0_rd_out[21]
    DIRECTION OUTPUT ;
    USE SIGNAL ;
    SHAPE ABUTMENT ;
    PORT
      LAYER metal2 ;
      RECT 67.795 0.000 67.865 0.210 ;
    END
  END r0_rd_out[21]
  PIN r0_rd_out[22]
    DIRECTION OUTPUT ;
    USE SIGNAL ;
    SHAPE ABUTMENT ;
    PORT
      LAYER metal2 ;
      RECT 68.365 0.000 68.435 0.210 ;
    END
  END r0_rd_out[22]
  PIN r0_rd_out[23]
    DIRECTION OUTPUT ;
    USE SIGNAL ;
    SHAPE ABUTMENT ;
    PORT
      LAYER metal2 ;
      RECT 68.935 0.000 69.005 0.210 ;
    END
  END r0_rd_out[23]
  PIN r0_rd_out[24]
    DIRECTION OUTPUT ;
    USE SIGNAL ;
    SHAPE ABUTMENT ;
    PORT
      LAYER metal2 ;
      RECT 69.505 0.000 69.575 0.210 ;
    END
  END r0_rd_out[24]
  PIN r0_rd_out[25]
    DIRECTION OUTPUT ;
    USE SIGNAL ;
    SHAPE ABUTMENT ;
    PORT
      LAYER metal2 ;
      RECT 70.075 0.000 70.145 0.210 ;
    END
  END r0_rd_out[25]
  PIN r0_rd_out[26]
    DIRECTION OUTPUT ;
    USE SIGNAL ;
    SHAPE ABUTMENT ;
    PORT
      LAYER metal2 ;
      RECT 70.645 0.000 70.715 0.210 ;
    END
  END r0_rd_out[26]
  PIN r0_rd_out[27]
    DIRECTION OUTPUT ;
    USE SIGNAL ;
    SHAPE ABUTMENT ;
    PORT
      LAYER metal2 ;
      RECT 71.215 0.000 71.285 0.210 ;
    END
  END r0_rd_out[27]
  PIN r0_rd_out[28]
    DIRECTION OUTPUT ;
    USE SIGNAL ;
    SHAPE ABUTMENT ;
    PORT
      LAYER metal2 ;
      RECT 71.785 0.000 71.855 0.210 ;
    END
  END r0_rd_out[28]
  PIN r0_rd_out[29]
    DIRECTION OUTPUT ;
    USE SIGNAL ;
    SHAPE ABUTMENT ;
    PORT
      LAYER metal2 ;
      RECT 72.355 0.000 72.425 0.210 ;
    END
  END r0_rd_out[29]
  PIN r0_rd_out[30]
    DIRECTION OUTPUT ;
    USE SIGNAL ;
    SHAPE ABUTMENT ;
    PORT
      LAYER metal2 ;
      RECT 72.925 0.000 72.995 0.210 ;
    END
  END r0_rd_out[30]
  PIN r0_rd_out[31]
    DIRECTION OUTPUT ;
    USE SIGNAL ;
    SHAPE ABUTMENT ;
    PORT
      LAYER metal2 ;
      RECT 73.495 0.000 73.565 0.210 ;
    END
  END r0_rd_out[31]
  PIN r0_rd_out[32]
    DIRECTION OUTPUT ;
    USE SIGNAL ;
    SHAPE ABUTMENT ;
    PORT
      LAYER metal2 ;
      RECT 74.065 0.000 74.135 0.210 ;
    END
  END r0_rd_out[32]
  PIN r0_rd_out[33]
    DIRECTION OUTPUT ;
    USE SIGNAL ;
    SHAPE ABUTMENT ;
    PORT
      LAYER metal2 ;
      RECT 74.635 0.000 74.705 0.210 ;
    END
  END r0_rd_out[33]
  PIN r0_rd_out[34]
    DIRECTION OUTPUT ;
    USE SIGNAL ;
    SHAPE ABUTMENT ;
    PORT
      LAYER metal2 ;
      RECT 75.205 0.000 75.275 0.210 ;
    END
  END r0_rd_out[34]
  PIN r0_rd_out[35]
    DIRECTION OUTPUT ;
    USE SIGNAL ;
    SHAPE ABUTMENT ;
    PORT
      LAYER metal2 ;
      RECT 75.775 0.000 75.845 0.210 ;
    END
  END r0_rd_out[35]
  PIN r0_rd_out[36]
    DIRECTION OUTPUT ;
    USE SIGNAL ;
    SHAPE ABUTMENT ;
    PORT
      LAYER metal2 ;
      RECT 76.345 0.000 76.415 0.210 ;
    END
  END r0_rd_out[36]
  PIN r0_rd_out[37]
    DIRECTION OUTPUT ;
    USE SIGNAL ;
    SHAPE ABUTMENT ;
    PORT
      LAYER metal2 ;
      RECT 76.915 0.000 76.985 0.210 ;
    END
  END r0_rd_out[37]
  PIN r0_rd_out[38]
    DIRECTION OUTPUT ;
    USE SIGNAL ;
    SHAPE ABUTMENT ;
    PORT
      LAYER metal2 ;
      RECT 77.485 0.000 77.555 0.210 ;
    END
  END r0_rd_out[38]
  PIN r0_rd_out[39]
    DIRECTION OUTPUT ;
    USE SIGNAL ;
    SHAPE ABUTMENT ;
    PORT
      LAYER metal2 ;
      RECT 78.055 0.000 78.125 0.210 ;
    END
  END r0_rd_out[39]
  PIN r0_rd_out[40]
    DIRECTION OUTPUT ;
    USE SIGNAL ;
    SHAPE ABUTMENT ;
    PORT
      LAYER metal2 ;
      RECT 78.625 0.000 78.695 0.210 ;
    END
  END r0_rd_out[40]
  PIN r0_rd_out[41]
    DIRECTION OUTPUT ;
    USE SIGNAL ;
    SHAPE ABUTMENT ;
    PORT
      LAYER metal2 ;
      RECT 79.195 0.000 79.265 0.210 ;
    END
  END r0_rd_out[41]
  PIN r0_rd_out[42]
    DIRECTION OUTPUT ;
    USE SIGNAL ;
    SHAPE ABUTMENT ;
    PORT
      LAYER metal2 ;
      RECT 79.765 0.000 79.835 0.210 ;
    END
  END r0_rd_out[42]
  PIN r0_rd_out[43]
    DIRECTION OUTPUT ;
    USE SIGNAL ;
    SHAPE ABUTMENT ;
    PORT
      LAYER metal2 ;
      RECT 80.335 0.000 80.405 0.210 ;
    END
  END r0_rd_out[43]
  PIN r0_rd_out[44]
    DIRECTION OUTPUT ;
    USE SIGNAL ;
    SHAPE ABUTMENT ;
    PORT
      LAYER metal2 ;
      RECT 80.905 0.000 80.975 0.210 ;
    END
  END r0_rd_out[44]
  PIN r0_rd_out[45]
    DIRECTION OUTPUT ;
    USE SIGNAL ;
    SHAPE ABUTMENT ;
    PORT
      LAYER metal2 ;
      RECT 81.475 0.000 81.545 0.210 ;
    END
  END r0_rd_out[45]
  PIN r0_rd_out[46]
    DIRECTION OUTPUT ;
    USE SIGNAL ;
    SHAPE ABUTMENT ;
    PORT
      LAYER metal2 ;
      RECT 82.045 0.000 82.115 0.210 ;
    END
  END r0_rd_out[46]
  PIN r0_rd_out[47]
    DIRECTION OUTPUT ;
    USE SIGNAL ;
    SHAPE ABUTMENT ;
    PORT
      LAYER metal2 ;
      RECT 82.615 0.000 82.685 0.210 ;
    END
  END r0_rd_out[47]
  PIN r0_rd_out[48]
    DIRECTION OUTPUT ;
    USE SIGNAL ;
    SHAPE ABUTMENT ;
    PORT
      LAYER metal2 ;
      RECT 83.185 0.000 83.255 0.210 ;
    END
  END r0_rd_out[48]
  PIN r0_rd_out[49]
    DIRECTION OUTPUT ;
    USE SIGNAL ;
    SHAPE ABUTMENT ;
    PORT
      LAYER metal2 ;
      RECT 83.755 0.000 83.825 0.210 ;
    END
  END r0_rd_out[49]
  PIN r0_rd_out[50]
    DIRECTION OUTPUT ;
    USE SIGNAL ;
    SHAPE ABUTMENT ;
    PORT
      LAYER metal2 ;
      RECT 84.325 0.000 84.395 0.210 ;
    END
  END r0_rd_out[50]
  PIN r0_rd_out[51]
    DIRECTION OUTPUT ;
    USE SIGNAL ;
    SHAPE ABUTMENT ;
    PORT
      LAYER metal2 ;
      RECT 84.895 0.000 84.965 0.210 ;
    END
  END r0_rd_out[51]
  PIN r0_rd_out[52]
    DIRECTION OUTPUT ;
    USE SIGNAL ;
    SHAPE ABUTMENT ;
    PORT
      LAYER metal2 ;
      RECT 85.465 0.000 85.535 0.210 ;
    END
  END r0_rd_out[52]
  PIN r0_rd_out[53]
    DIRECTION OUTPUT ;
    USE SIGNAL ;
    SHAPE ABUTMENT ;
    PORT
      LAYER metal2 ;
      RECT 86.035 0.000 86.105 0.210 ;
    END
  END r0_rd_out[53]
  PIN r0_rd_out[54]
    DIRECTION OUTPUT ;
    USE SIGNAL ;
    SHAPE ABUTMENT ;
    PORT
      LAYER metal2 ;
      RECT 86.605 0.000 86.675 0.210 ;
    END
  END r0_rd_out[54]
  PIN r0_rd_out[55]
    DIRECTION OUTPUT ;
    USE SIGNAL ;
    SHAPE ABUTMENT ;
    PORT
      LAYER metal2 ;
      RECT 87.175 0.000 87.245 0.210 ;
    END
  END r0_rd_out[55]
  PIN r0_rd_out[56]
    DIRECTION OUTPUT ;
    USE SIGNAL ;
    SHAPE ABUTMENT ;
    PORT
      LAYER metal2 ;
      RECT 87.745 0.000 87.815 0.210 ;
    END
  END r0_rd_out[56]
  PIN r0_rd_out[57]
    DIRECTION OUTPUT ;
    USE SIGNAL ;
    SHAPE ABUTMENT ;
    PORT
      LAYER metal2 ;
      RECT 88.315 0.000 88.385 0.210 ;
    END
  END r0_rd_out[57]
  PIN r0_rd_out[58]
    DIRECTION OUTPUT ;
    USE SIGNAL ;
    SHAPE ABUTMENT ;
    PORT
      LAYER metal2 ;
      RECT 88.885 0.000 88.955 0.210 ;
    END
  END r0_rd_out[58]
  PIN r0_rd_out[59]
    DIRECTION OUTPUT ;
    USE SIGNAL ;
    SHAPE ABUTMENT ;
    PORT
      LAYER metal2 ;
      RECT 89.455 0.000 89.525 0.210 ;
    END
  END r0_rd_out[59]
  PIN r0_rd_out[60]
    DIRECTION OUTPUT ;
    USE SIGNAL ;
    SHAPE ABUTMENT ;
    PORT
      LAYER metal2 ;
      RECT 90.025 0.000 90.095 0.210 ;
    END
  END r0_rd_out[60]
  PIN r0_rd_out[61]
    DIRECTION OUTPUT ;
    USE SIGNAL ;
    SHAPE ABUTMENT ;
    PORT
      LAYER metal2 ;
      RECT 90.595 0.000 90.665 0.210 ;
    END
  END r0_rd_out[61]
  PIN r0_rd_out[62]
    DIRECTION OUTPUT ;
    USE SIGNAL ;
    SHAPE ABUTMENT ;
    PORT
      LAYER metal2 ;
      RECT 91.165 0.000 91.235 0.210 ;
    END
  END r0_rd_out[62]
  PIN r0_rd_out[63]
    DIRECTION OUTPUT ;
    USE SIGNAL ;
    SHAPE ABUTMENT ;
    PORT
      LAYER metal2 ;
      RECT 91.735 0.000 91.805 0.210 ;
    END
  END r0_rd_out[63]
  PIN r0_rd_out[64]
    DIRECTION OUTPUT ;
    USE SIGNAL ;
    SHAPE ABUTMENT ;
    PORT
      LAYER metal2 ;
      RECT 92.305 0.000 92.375 0.210 ;
    END
  END r0_rd_out[64]
  PIN r0_rd_out[65]
    DIRECTION OUTPUT ;
    USE SIGNAL ;
    SHAPE ABUTMENT ;
    PORT
      LAYER metal2 ;
      RECT 92.875 0.000 92.945 0.210 ;
    END
  END r0_rd_out[65]
  PIN r0_rd_out[66]
    DIRECTION OUTPUT ;
    USE SIGNAL ;
    SHAPE ABUTMENT ;
    PORT
      LAYER metal2 ;
      RECT 93.445 0.000 93.515 0.210 ;
    END
  END r0_rd_out[66]
  PIN r0_rd_out[67]
    DIRECTION OUTPUT ;
    USE SIGNAL ;
    SHAPE ABUTMENT ;
    PORT
      LAYER metal2 ;
      RECT 94.015 0.000 94.085 0.210 ;
    END
  END r0_rd_out[67]
  PIN r0_rd_out[68]
    DIRECTION OUTPUT ;
    USE SIGNAL ;
    SHAPE ABUTMENT ;
    PORT
      LAYER metal2 ;
      RECT 94.585 0.000 94.655 0.210 ;
    END
  END r0_rd_out[68]
  PIN r0_rd_out[69]
    DIRECTION OUTPUT ;
    USE SIGNAL ;
    SHAPE ABUTMENT ;
    PORT
      LAYER metal2 ;
      RECT 95.155 0.000 95.225 0.210 ;
    END
  END r0_rd_out[69]
  PIN r0_rd_out[70]
    DIRECTION OUTPUT ;
    USE SIGNAL ;
    SHAPE ABUTMENT ;
    PORT
      LAYER metal2 ;
      RECT 95.725 0.000 95.795 0.210 ;
    END
  END r0_rd_out[70]
  PIN r0_rd_out[71]
    DIRECTION OUTPUT ;
    USE SIGNAL ;
    SHAPE ABUTMENT ;
    PORT
      LAYER metal2 ;
      RECT 96.295 0.000 96.365 0.210 ;
    END
  END r0_rd_out[71]
  PIN r0_rd_out[72]
    DIRECTION OUTPUT ;
    USE SIGNAL ;
    SHAPE ABUTMENT ;
    PORT
      LAYER metal2 ;
      RECT 96.865 0.000 96.935 0.210 ;
    END
  END r0_rd_out[72]
  PIN r0_rd_out[73]
    DIRECTION OUTPUT ;
    USE SIGNAL ;
    SHAPE ABUTMENT ;
    PORT
      LAYER metal2 ;
      RECT 97.435 0.000 97.505 0.210 ;
    END
  END r0_rd_out[73]
  PIN r0_rd_out[74]
    DIRECTION OUTPUT ;
    USE SIGNAL ;
    SHAPE ABUTMENT ;
    PORT
      LAYER metal2 ;
      RECT 98.005 0.000 98.075 0.210 ;
    END
  END r0_rd_out[74]
  PIN r0_rd_out[75]
    DIRECTION OUTPUT ;
    USE SIGNAL ;
    SHAPE ABUTMENT ;
    PORT
      LAYER metal2 ;
      RECT 98.575 0.000 98.645 0.210 ;
    END
  END r0_rd_out[75]
  PIN r0_rd_out[76]
    DIRECTION OUTPUT ;
    USE SIGNAL ;
    SHAPE ABUTMENT ;
    PORT
      LAYER metal2 ;
      RECT 99.145 0.000 99.215 0.210 ;
    END
  END r0_rd_out[76]
  PIN r0_rd_out[77]
    DIRECTION OUTPUT ;
    USE SIGNAL ;
    SHAPE ABUTMENT ;
    PORT
      LAYER metal2 ;
      RECT 99.715 0.000 99.785 0.210 ;
    END
  END r0_rd_out[77]
  PIN r0_rd_out[78]
    DIRECTION OUTPUT ;
    USE SIGNAL ;
    SHAPE ABUTMENT ;
    PORT
      LAYER metal2 ;
      RECT 100.285 0.000 100.355 0.210 ;
    END
  END r0_rd_out[78]
  PIN r0_rd_out[79]
    DIRECTION OUTPUT ;
    USE SIGNAL ;
    SHAPE ABUTMENT ;
    PORT
      LAYER metal2 ;
      RECT 100.855 0.000 100.925 0.210 ;
    END
  END r0_rd_out[79]
  PIN r0_rd_out[80]
    DIRECTION OUTPUT ;
    USE SIGNAL ;
    SHAPE ABUTMENT ;
    PORT
      LAYER metal2 ;
      RECT 101.425 0.000 101.495 0.210 ;
    END
  END r0_rd_out[80]
  PIN r0_rd_out[81]
    DIRECTION OUTPUT ;
    USE SIGNAL ;
    SHAPE ABUTMENT ;
    PORT
      LAYER metal2 ;
      RECT 101.995 0.000 102.065 0.210 ;
    END
  END r0_rd_out[81]
  PIN r0_rd_out[82]
    DIRECTION OUTPUT ;
    USE SIGNAL ;
    SHAPE ABUTMENT ;
    PORT
      LAYER metal2 ;
      RECT 102.565 0.000 102.635 0.210 ;
    END
  END r0_rd_out[82]
  PIN r0_rd_out[83]
    DIRECTION OUTPUT ;
    USE SIGNAL ;
    SHAPE ABUTMENT ;
    PORT
      LAYER metal2 ;
      RECT 103.135 0.000 103.205 0.210 ;
    END
  END r0_rd_out[83]
  PIN r0_rd_out[84]
    DIRECTION OUTPUT ;
    USE SIGNAL ;
    SHAPE ABUTMENT ;
    PORT
      LAYER metal2 ;
      RECT 103.705 0.000 103.775 0.210 ;
    END
  END r0_rd_out[84]
  PIN r0_rd_out[85]
    DIRECTION OUTPUT ;
    USE SIGNAL ;
    SHAPE ABUTMENT ;
    PORT
      LAYER metal2 ;
      RECT 104.275 0.000 104.345 0.210 ;
    END
  END r0_rd_out[85]
  PIN r0_rd_out[86]
    DIRECTION OUTPUT ;
    USE SIGNAL ;
    SHAPE ABUTMENT ;
    PORT
      LAYER metal2 ;
      RECT 104.845 0.000 104.915 0.210 ;
    END
  END r0_rd_out[86]
  PIN r0_rd_out[87]
    DIRECTION OUTPUT ;
    USE SIGNAL ;
    SHAPE ABUTMENT ;
    PORT
      LAYER metal2 ;
      RECT 105.415 0.000 105.485 0.210 ;
    END
  END r0_rd_out[87]
  PIN r0_rd_out[88]
    DIRECTION OUTPUT ;
    USE SIGNAL ;
    SHAPE ABUTMENT ;
    PORT
      LAYER metal2 ;
      RECT 105.985 0.000 106.055 0.210 ;
    END
  END r0_rd_out[88]
  PIN r0_rd_out[89]
    DIRECTION OUTPUT ;
    USE SIGNAL ;
    SHAPE ABUTMENT ;
    PORT
      LAYER metal2 ;
      RECT 106.555 0.000 106.625 0.210 ;
    END
  END r0_rd_out[89]
  PIN r0_rd_out[90]
    DIRECTION OUTPUT ;
    USE SIGNAL ;
    SHAPE ABUTMENT ;
    PORT
      LAYER metal2 ;
      RECT 107.125 0.000 107.195 0.210 ;
    END
  END r0_rd_out[90]
  PIN r0_rd_out[91]
    DIRECTION OUTPUT ;
    USE SIGNAL ;
    SHAPE ABUTMENT ;
    PORT
      LAYER metal2 ;
      RECT 107.695 0.000 107.765 0.210 ;
    END
  END r0_rd_out[91]
  PIN r0_rd_out[92]
    DIRECTION OUTPUT ;
    USE SIGNAL ;
    SHAPE ABUTMENT ;
    PORT
      LAYER metal2 ;
      RECT 108.265 0.000 108.335 0.210 ;
    END
  END r0_rd_out[92]
  PIN r0_rd_out[93]
    DIRECTION OUTPUT ;
    USE SIGNAL ;
    SHAPE ABUTMENT ;
    PORT
      LAYER metal2 ;
      RECT 108.835 0.000 108.905 0.210 ;
    END
  END r0_rd_out[93]
  PIN r0_rd_out[94]
    DIRECTION OUTPUT ;
    USE SIGNAL ;
    SHAPE ABUTMENT ;
    PORT
      LAYER metal2 ;
      RECT 109.405 0.000 109.475 0.210 ;
    END
  END r0_rd_out[94]
  PIN r0_rd_out[95]
    DIRECTION OUTPUT ;
    USE SIGNAL ;
    SHAPE ABUTMENT ;
    PORT
      LAYER metal2 ;
      RECT 109.975 0.000 110.045 0.210 ;
    END
  END r0_rd_out[95]
  PIN r0_rd_out[96]
    DIRECTION OUTPUT ;
    USE SIGNAL ;
    SHAPE ABUTMENT ;
    PORT
      LAYER metal2 ;
      RECT 110.545 0.000 110.615 0.210 ;
    END
  END r0_rd_out[96]
  PIN r0_rd_out[97]
    DIRECTION OUTPUT ;
    USE SIGNAL ;
    SHAPE ABUTMENT ;
    PORT
      LAYER metal2 ;
      RECT 55.825 216.790 55.895 217.000 ;
    END
  END r0_rd_out[97]
  PIN r0_rd_out[98]
    DIRECTION OUTPUT ;
    USE SIGNAL ;
    SHAPE ABUTMENT ;
    PORT
      LAYER metal2 ;
      RECT 56.395 216.790 56.465 217.000 ;
    END
  END r0_rd_out[98]
  PIN r0_rd_out[99]
    DIRECTION OUTPUT ;
    USE SIGNAL ;
    SHAPE ABUTMENT ;
    PORT
      LAYER metal2 ;
      RECT 56.965 216.790 57.035 217.000 ;
    END
  END r0_rd_out[99]
  PIN r0_rd_out[100]
    DIRECTION OUTPUT ;
    USE SIGNAL ;
    SHAPE ABUTMENT ;
    PORT
      LAYER metal2 ;
      RECT 57.535 216.790 57.605 217.000 ;
    END
  END r0_rd_out[100]
  PIN r0_rd_out[101]
    DIRECTION OUTPUT ;
    USE SIGNAL ;
    SHAPE ABUTMENT ;
    PORT
      LAYER metal2 ;
      RECT 58.105 216.790 58.175 217.000 ;
    END
  END r0_rd_out[101]
  PIN r0_rd_out[102]
    DIRECTION OUTPUT ;
    USE SIGNAL ;
    SHAPE ABUTMENT ;
    PORT
      LAYER metal2 ;
      RECT 58.675 216.790 58.745 217.000 ;
    END
  END r0_rd_out[102]
  PIN r0_rd_out[103]
    DIRECTION OUTPUT ;
    USE SIGNAL ;
    SHAPE ABUTMENT ;
    PORT
      LAYER metal2 ;
      RECT 59.245 216.790 59.315 217.000 ;
    END
  END r0_rd_out[103]
  PIN r0_rd_out[104]
    DIRECTION OUTPUT ;
    USE SIGNAL ;
    SHAPE ABUTMENT ;
    PORT
      LAYER metal2 ;
      RECT 59.815 216.790 59.885 217.000 ;
    END
  END r0_rd_out[104]
  PIN r0_rd_out[105]
    DIRECTION OUTPUT ;
    USE SIGNAL ;
    SHAPE ABUTMENT ;
    PORT
      LAYER metal2 ;
      RECT 60.385 216.790 60.455 217.000 ;
    END
  END r0_rd_out[105]
  PIN r0_rd_out[106]
    DIRECTION OUTPUT ;
    USE SIGNAL ;
    SHAPE ABUTMENT ;
    PORT
      LAYER metal2 ;
      RECT 60.955 216.790 61.025 217.000 ;
    END
  END r0_rd_out[106]
  PIN r0_rd_out[107]
    DIRECTION OUTPUT ;
    USE SIGNAL ;
    SHAPE ABUTMENT ;
    PORT
      LAYER metal2 ;
      RECT 61.525 216.790 61.595 217.000 ;
    END
  END r0_rd_out[107]
  PIN r0_rd_out[108]
    DIRECTION OUTPUT ;
    USE SIGNAL ;
    SHAPE ABUTMENT ;
    PORT
      LAYER metal2 ;
      RECT 62.095 216.790 62.165 217.000 ;
    END
  END r0_rd_out[108]
  PIN r0_rd_out[109]
    DIRECTION OUTPUT ;
    USE SIGNAL ;
    SHAPE ABUTMENT ;
    PORT
      LAYER metal2 ;
      RECT 62.665 216.790 62.735 217.000 ;
    END
  END r0_rd_out[109]
  PIN r0_rd_out[110]
    DIRECTION OUTPUT ;
    USE SIGNAL ;
    SHAPE ABUTMENT ;
    PORT
      LAYER metal2 ;
      RECT 63.235 216.790 63.305 217.000 ;
    END
  END r0_rd_out[110]
  PIN r0_rd_out[111]
    DIRECTION OUTPUT ;
    USE SIGNAL ;
    SHAPE ABUTMENT ;
    PORT
      LAYER metal2 ;
      RECT 63.805 216.790 63.875 217.000 ;
    END
  END r0_rd_out[111]
  PIN r0_rd_out[112]
    DIRECTION OUTPUT ;
    USE SIGNAL ;
    SHAPE ABUTMENT ;
    PORT
      LAYER metal2 ;
      RECT 64.375 216.790 64.445 217.000 ;
    END
  END r0_rd_out[112]
  PIN r0_rd_out[113]
    DIRECTION OUTPUT ;
    USE SIGNAL ;
    SHAPE ABUTMENT ;
    PORT
      LAYER metal2 ;
      RECT 64.945 216.790 65.015 217.000 ;
    END
  END r0_rd_out[113]
  PIN r0_rd_out[114]
    DIRECTION OUTPUT ;
    USE SIGNAL ;
    SHAPE ABUTMENT ;
    PORT
      LAYER metal2 ;
      RECT 65.515 216.790 65.585 217.000 ;
    END
  END r0_rd_out[114]
  PIN r0_rd_out[115]
    DIRECTION OUTPUT ;
    USE SIGNAL ;
    SHAPE ABUTMENT ;
    PORT
      LAYER metal2 ;
      RECT 66.085 216.790 66.155 217.000 ;
    END
  END r0_rd_out[115]
  PIN r0_rd_out[116]
    DIRECTION OUTPUT ;
    USE SIGNAL ;
    SHAPE ABUTMENT ;
    PORT
      LAYER metal2 ;
      RECT 66.655 216.790 66.725 217.000 ;
    END
  END r0_rd_out[116]
  PIN r0_rd_out[117]
    DIRECTION OUTPUT ;
    USE SIGNAL ;
    SHAPE ABUTMENT ;
    PORT
      LAYER metal2 ;
      RECT 67.225 216.790 67.295 217.000 ;
    END
  END r0_rd_out[117]
  PIN r0_rd_out[118]
    DIRECTION OUTPUT ;
    USE SIGNAL ;
    SHAPE ABUTMENT ;
    PORT
      LAYER metal2 ;
      RECT 67.795 216.790 67.865 217.000 ;
    END
  END r0_rd_out[118]
  PIN r0_rd_out[119]
    DIRECTION OUTPUT ;
    USE SIGNAL ;
    SHAPE ABUTMENT ;
    PORT
      LAYER metal2 ;
      RECT 68.365 216.790 68.435 217.000 ;
    END
  END r0_rd_out[119]
  PIN r0_rd_out[120]
    DIRECTION OUTPUT ;
    USE SIGNAL ;
    SHAPE ABUTMENT ;
    PORT
      LAYER metal2 ;
      RECT 68.935 216.790 69.005 217.000 ;
    END
  END r0_rd_out[120]
  PIN r0_rd_out[121]
    DIRECTION OUTPUT ;
    USE SIGNAL ;
    SHAPE ABUTMENT ;
    PORT
      LAYER metal2 ;
      RECT 69.505 216.790 69.575 217.000 ;
    END
  END r0_rd_out[121]
  PIN r0_rd_out[122]
    DIRECTION OUTPUT ;
    USE SIGNAL ;
    SHAPE ABUTMENT ;
    PORT
      LAYER metal2 ;
      RECT 70.075 216.790 70.145 217.000 ;
    END
  END r0_rd_out[122]
  PIN r0_rd_out[123]
    DIRECTION OUTPUT ;
    USE SIGNAL ;
    SHAPE ABUTMENT ;
    PORT
      LAYER metal2 ;
      RECT 70.645 216.790 70.715 217.000 ;
    END
  END r0_rd_out[123]
  PIN r0_rd_out[124]
    DIRECTION OUTPUT ;
    USE SIGNAL ;
    SHAPE ABUTMENT ;
    PORT
      LAYER metal2 ;
      RECT 71.215 216.790 71.285 217.000 ;
    END
  END r0_rd_out[124]
  PIN r0_rd_out[125]
    DIRECTION OUTPUT ;
    USE SIGNAL ;
    SHAPE ABUTMENT ;
    PORT
      LAYER metal2 ;
      RECT 71.785 216.790 71.855 217.000 ;
    END
  END r0_rd_out[125]
  PIN r0_rd_out[126]
    DIRECTION OUTPUT ;
    USE SIGNAL ;
    SHAPE ABUTMENT ;
    PORT
      LAYER metal2 ;
      RECT 72.355 216.790 72.425 217.000 ;
    END
  END r0_rd_out[126]
  PIN r0_rd_out[127]
    DIRECTION OUTPUT ;
    USE SIGNAL ;
    SHAPE ABUTMENT ;
    PORT
      LAYER metal2 ;
      RECT 72.925 216.790 72.995 217.000 ;
    END
  END r0_rd_out[127]
  PIN r0_rd_out[128]
    DIRECTION OUTPUT ;
    USE SIGNAL ;
    SHAPE ABUTMENT ;
    PORT
      LAYER metal2 ;
      RECT 73.495 216.790 73.565 217.000 ;
    END
  END r0_rd_out[128]
  PIN r0_rd_out[129]
    DIRECTION OUTPUT ;
    USE SIGNAL ;
    SHAPE ABUTMENT ;
    PORT
      LAYER metal2 ;
      RECT 74.065 216.790 74.135 217.000 ;
    END
  END r0_rd_out[129]
  PIN r0_rd_out[130]
    DIRECTION OUTPUT ;
    USE SIGNAL ;
    SHAPE ABUTMENT ;
    PORT
      LAYER metal2 ;
      RECT 74.635 216.790 74.705 217.000 ;
    END
  END r0_rd_out[130]
  PIN r0_rd_out[131]
    DIRECTION OUTPUT ;
    USE SIGNAL ;
    SHAPE ABUTMENT ;
    PORT
      LAYER metal2 ;
      RECT 75.205 216.790 75.275 217.000 ;
    END
  END r0_rd_out[131]
  PIN r0_rd_out[132]
    DIRECTION OUTPUT ;
    USE SIGNAL ;
    SHAPE ABUTMENT ;
    PORT
      LAYER metal2 ;
      RECT 75.775 216.790 75.845 217.000 ;
    END
  END r0_rd_out[132]
  PIN r0_rd_out[133]
    DIRECTION OUTPUT ;
    USE SIGNAL ;
    SHAPE ABUTMENT ;
    PORT
      LAYER metal2 ;
      RECT 76.345 216.790 76.415 217.000 ;
    END
  END r0_rd_out[133]
  PIN r0_rd_out[134]
    DIRECTION OUTPUT ;
    USE SIGNAL ;
    SHAPE ABUTMENT ;
    PORT
      LAYER metal2 ;
      RECT 76.915 216.790 76.985 217.000 ;
    END
  END r0_rd_out[134]
  PIN r0_rd_out[135]
    DIRECTION OUTPUT ;
    USE SIGNAL ;
    SHAPE ABUTMENT ;
    PORT
      LAYER metal2 ;
      RECT 77.485 216.790 77.555 217.000 ;
    END
  END r0_rd_out[135]
  PIN r0_rd_out[136]
    DIRECTION OUTPUT ;
    USE SIGNAL ;
    SHAPE ABUTMENT ;
    PORT
      LAYER metal2 ;
      RECT 78.055 216.790 78.125 217.000 ;
    END
  END r0_rd_out[136]
  PIN r0_rd_out[137]
    DIRECTION OUTPUT ;
    USE SIGNAL ;
    SHAPE ABUTMENT ;
    PORT
      LAYER metal2 ;
      RECT 78.625 216.790 78.695 217.000 ;
    END
  END r0_rd_out[137]
  PIN r0_rd_out[138]
    DIRECTION OUTPUT ;
    USE SIGNAL ;
    SHAPE ABUTMENT ;
    PORT
      LAYER metal2 ;
      RECT 79.195 216.790 79.265 217.000 ;
    END
  END r0_rd_out[138]
  PIN r0_rd_out[139]
    DIRECTION OUTPUT ;
    USE SIGNAL ;
    SHAPE ABUTMENT ;
    PORT
      LAYER metal2 ;
      RECT 79.765 216.790 79.835 217.000 ;
    END
  END r0_rd_out[139]
  PIN r0_rd_out[140]
    DIRECTION OUTPUT ;
    USE SIGNAL ;
    SHAPE ABUTMENT ;
    PORT
      LAYER metal2 ;
      RECT 80.335 216.790 80.405 217.000 ;
    END
  END r0_rd_out[140]
  PIN r0_rd_out[141]
    DIRECTION OUTPUT ;
    USE SIGNAL ;
    SHAPE ABUTMENT ;
    PORT
      LAYER metal2 ;
      RECT 80.905 216.790 80.975 217.000 ;
    END
  END r0_rd_out[141]
  PIN r0_rd_out[142]
    DIRECTION OUTPUT ;
    USE SIGNAL ;
    SHAPE ABUTMENT ;
    PORT
      LAYER metal2 ;
      RECT 81.475 216.790 81.545 217.000 ;
    END
  END r0_rd_out[142]
  PIN r0_rd_out[143]
    DIRECTION OUTPUT ;
    USE SIGNAL ;
    SHAPE ABUTMENT ;
    PORT
      LAYER metal2 ;
      RECT 82.045 216.790 82.115 217.000 ;
    END
  END r0_rd_out[143]
  PIN r0_rd_out[144]
    DIRECTION OUTPUT ;
    USE SIGNAL ;
    SHAPE ABUTMENT ;
    PORT
      LAYER metal2 ;
      RECT 82.615 216.790 82.685 217.000 ;
    END
  END r0_rd_out[144]
  PIN r0_rd_out[145]
    DIRECTION OUTPUT ;
    USE SIGNAL ;
    SHAPE ABUTMENT ;
    PORT
      LAYER metal2 ;
      RECT 83.185 216.790 83.255 217.000 ;
    END
  END r0_rd_out[145]
  PIN r0_rd_out[146]
    DIRECTION OUTPUT ;
    USE SIGNAL ;
    SHAPE ABUTMENT ;
    PORT
      LAYER metal2 ;
      RECT 83.755 216.790 83.825 217.000 ;
    END
  END r0_rd_out[146]
  PIN r0_rd_out[147]
    DIRECTION OUTPUT ;
    USE SIGNAL ;
    SHAPE ABUTMENT ;
    PORT
      LAYER metal2 ;
      RECT 84.325 216.790 84.395 217.000 ;
    END
  END r0_rd_out[147]
  PIN r0_rd_out[148]
    DIRECTION OUTPUT ;
    USE SIGNAL ;
    SHAPE ABUTMENT ;
    PORT
      LAYER metal2 ;
      RECT 84.895 216.790 84.965 217.000 ;
    END
  END r0_rd_out[148]
  PIN r0_rd_out[149]
    DIRECTION OUTPUT ;
    USE SIGNAL ;
    SHAPE ABUTMENT ;
    PORT
      LAYER metal2 ;
      RECT 85.465 216.790 85.535 217.000 ;
    END
  END r0_rd_out[149]
  PIN r0_rd_out[150]
    DIRECTION OUTPUT ;
    USE SIGNAL ;
    SHAPE ABUTMENT ;
    PORT
      LAYER metal2 ;
      RECT 86.035 216.790 86.105 217.000 ;
    END
  END r0_rd_out[150]
  PIN r0_rd_out[151]
    DIRECTION OUTPUT ;
    USE SIGNAL ;
    SHAPE ABUTMENT ;
    PORT
      LAYER metal2 ;
      RECT 86.605 216.790 86.675 217.000 ;
    END
  END r0_rd_out[151]
  PIN r0_rd_out[152]
    DIRECTION OUTPUT ;
    USE SIGNAL ;
    SHAPE ABUTMENT ;
    PORT
      LAYER metal2 ;
      RECT 87.175 216.790 87.245 217.000 ;
    END
  END r0_rd_out[152]
  PIN r0_rd_out[153]
    DIRECTION OUTPUT ;
    USE SIGNAL ;
    SHAPE ABUTMENT ;
    PORT
      LAYER metal2 ;
      RECT 87.745 216.790 87.815 217.000 ;
    END
  END r0_rd_out[153]
  PIN r0_rd_out[154]
    DIRECTION OUTPUT ;
    USE SIGNAL ;
    SHAPE ABUTMENT ;
    PORT
      LAYER metal2 ;
      RECT 88.315 216.790 88.385 217.000 ;
    END
  END r0_rd_out[154]
  PIN r0_rd_out[155]
    DIRECTION OUTPUT ;
    USE SIGNAL ;
    SHAPE ABUTMENT ;
    PORT
      LAYER metal2 ;
      RECT 88.885 216.790 88.955 217.000 ;
    END
  END r0_rd_out[155]
  PIN r0_rd_out[156]
    DIRECTION OUTPUT ;
    USE SIGNAL ;
    SHAPE ABUTMENT ;
    PORT
      LAYER metal2 ;
      RECT 89.455 216.790 89.525 217.000 ;
    END
  END r0_rd_out[156]
  PIN r0_rd_out[157]
    DIRECTION OUTPUT ;
    USE SIGNAL ;
    SHAPE ABUTMENT ;
    PORT
      LAYER metal2 ;
      RECT 90.025 216.790 90.095 217.000 ;
    END
  END r0_rd_out[157]
  PIN r0_rd_out[158]
    DIRECTION OUTPUT ;
    USE SIGNAL ;
    SHAPE ABUTMENT ;
    PORT
      LAYER metal2 ;
      RECT 90.595 216.790 90.665 217.000 ;
    END
  END r0_rd_out[158]
  PIN r0_rd_out[159]
    DIRECTION OUTPUT ;
    USE SIGNAL ;
    SHAPE ABUTMENT ;
    PORT
      LAYER metal2 ;
      RECT 91.165 216.790 91.235 217.000 ;
    END
  END r0_rd_out[159]
  PIN r0_rd_out[160]
    DIRECTION OUTPUT ;
    USE SIGNAL ;
    SHAPE ABUTMENT ;
    PORT
      LAYER metal2 ;
      RECT 91.735 216.790 91.805 217.000 ;
    END
  END r0_rd_out[160]
  PIN r0_rd_out[161]
    DIRECTION OUTPUT ;
    USE SIGNAL ;
    SHAPE ABUTMENT ;
    PORT
      LAYER metal2 ;
      RECT 92.305 216.790 92.375 217.000 ;
    END
  END r0_rd_out[161]
  PIN r0_rd_out[162]
    DIRECTION OUTPUT ;
    USE SIGNAL ;
    SHAPE ABUTMENT ;
    PORT
      LAYER metal2 ;
      RECT 92.875 216.790 92.945 217.000 ;
    END
  END r0_rd_out[162]
  PIN r0_rd_out[163]
    DIRECTION OUTPUT ;
    USE SIGNAL ;
    SHAPE ABUTMENT ;
    PORT
      LAYER metal2 ;
      RECT 93.445 216.790 93.515 217.000 ;
    END
  END r0_rd_out[163]
  PIN r0_rd_out[164]
    DIRECTION OUTPUT ;
    USE SIGNAL ;
    SHAPE ABUTMENT ;
    PORT
      LAYER metal2 ;
      RECT 94.015 216.790 94.085 217.000 ;
    END
  END r0_rd_out[164]
  PIN r0_rd_out[165]
    DIRECTION OUTPUT ;
    USE SIGNAL ;
    SHAPE ABUTMENT ;
    PORT
      LAYER metal2 ;
      RECT 94.585 216.790 94.655 217.000 ;
    END
  END r0_rd_out[165]
  PIN r0_rd_out[166]
    DIRECTION OUTPUT ;
    USE SIGNAL ;
    SHAPE ABUTMENT ;
    PORT
      LAYER metal2 ;
      RECT 95.155 216.790 95.225 217.000 ;
    END
  END r0_rd_out[166]
  PIN r0_rd_out[167]
    DIRECTION OUTPUT ;
    USE SIGNAL ;
    SHAPE ABUTMENT ;
    PORT
      LAYER metal2 ;
      RECT 95.725 216.790 95.795 217.000 ;
    END
  END r0_rd_out[167]
  PIN r0_rd_out[168]
    DIRECTION OUTPUT ;
    USE SIGNAL ;
    SHAPE ABUTMENT ;
    PORT
      LAYER metal2 ;
      RECT 96.295 216.790 96.365 217.000 ;
    END
  END r0_rd_out[168]
  PIN r0_rd_out[169]
    DIRECTION OUTPUT ;
    USE SIGNAL ;
    SHAPE ABUTMENT ;
    PORT
      LAYER metal2 ;
      RECT 96.865 216.790 96.935 217.000 ;
    END
  END r0_rd_out[169]
  PIN r0_rd_out[170]
    DIRECTION OUTPUT ;
    USE SIGNAL ;
    SHAPE ABUTMENT ;
    PORT
      LAYER metal2 ;
      RECT 97.435 216.790 97.505 217.000 ;
    END
  END r0_rd_out[170]
  PIN r0_rd_out[171]
    DIRECTION OUTPUT ;
    USE SIGNAL ;
    SHAPE ABUTMENT ;
    PORT
      LAYER metal2 ;
      RECT 98.005 216.790 98.075 217.000 ;
    END
  END r0_rd_out[171]
  PIN r0_rd_out[172]
    DIRECTION OUTPUT ;
    USE SIGNAL ;
    SHAPE ABUTMENT ;
    PORT
      LAYER metal2 ;
      RECT 98.575 216.790 98.645 217.000 ;
    END
  END r0_rd_out[172]
  PIN r0_rd_out[173]
    DIRECTION OUTPUT ;
    USE SIGNAL ;
    SHAPE ABUTMENT ;
    PORT
      LAYER metal2 ;
      RECT 99.145 216.790 99.215 217.000 ;
    END
  END r0_rd_out[173]
  PIN r0_rd_out[174]
    DIRECTION OUTPUT ;
    USE SIGNAL ;
    SHAPE ABUTMENT ;
    PORT
      LAYER metal2 ;
      RECT 99.715 216.790 99.785 217.000 ;
    END
  END r0_rd_out[174]
  PIN r0_rd_out[175]
    DIRECTION OUTPUT ;
    USE SIGNAL ;
    SHAPE ABUTMENT ;
    PORT
      LAYER metal2 ;
      RECT 100.285 216.790 100.355 217.000 ;
    END
  END r0_rd_out[175]
  PIN r0_rd_out[176]
    DIRECTION OUTPUT ;
    USE SIGNAL ;
    SHAPE ABUTMENT ;
    PORT
      LAYER metal2 ;
      RECT 100.855 216.790 100.925 217.000 ;
    END
  END r0_rd_out[176]
  PIN r0_rd_out[177]
    DIRECTION OUTPUT ;
    USE SIGNAL ;
    SHAPE ABUTMENT ;
    PORT
      LAYER metal2 ;
      RECT 101.425 216.790 101.495 217.000 ;
    END
  END r0_rd_out[177]
  PIN r0_rd_out[178]
    DIRECTION OUTPUT ;
    USE SIGNAL ;
    SHAPE ABUTMENT ;
    PORT
      LAYER metal2 ;
      RECT 101.995 216.790 102.065 217.000 ;
    END
  END r0_rd_out[178]
  PIN r0_rd_out[179]
    DIRECTION OUTPUT ;
    USE SIGNAL ;
    SHAPE ABUTMENT ;
    PORT
      LAYER metal2 ;
      RECT 102.565 216.790 102.635 217.000 ;
    END
  END r0_rd_out[179]
  PIN r0_rd_out[180]
    DIRECTION OUTPUT ;
    USE SIGNAL ;
    SHAPE ABUTMENT ;
    PORT
      LAYER metal2 ;
      RECT 103.135 216.790 103.205 217.000 ;
    END
  END r0_rd_out[180]
  PIN r0_rd_out[181]
    DIRECTION OUTPUT ;
    USE SIGNAL ;
    SHAPE ABUTMENT ;
    PORT
      LAYER metal2 ;
      RECT 103.705 216.790 103.775 217.000 ;
    END
  END r0_rd_out[181]
  PIN r0_rd_out[182]
    DIRECTION OUTPUT ;
    USE SIGNAL ;
    SHAPE ABUTMENT ;
    PORT
      LAYER metal2 ;
      RECT 104.275 216.790 104.345 217.000 ;
    END
  END r0_rd_out[182]
  PIN r0_rd_out[183]
    DIRECTION OUTPUT ;
    USE SIGNAL ;
    SHAPE ABUTMENT ;
    PORT
      LAYER metal2 ;
      RECT 104.845 216.790 104.915 217.000 ;
    END
  END r0_rd_out[183]
  PIN r0_rd_out[184]
    DIRECTION OUTPUT ;
    USE SIGNAL ;
    SHAPE ABUTMENT ;
    PORT
      LAYER metal2 ;
      RECT 105.415 216.790 105.485 217.000 ;
    END
  END r0_rd_out[184]
  PIN r0_rd_out[185]
    DIRECTION OUTPUT ;
    USE SIGNAL ;
    SHAPE ABUTMENT ;
    PORT
      LAYER metal2 ;
      RECT 105.985 216.790 106.055 217.000 ;
    END
  END r0_rd_out[185]
  PIN r0_rd_out[186]
    DIRECTION OUTPUT ;
    USE SIGNAL ;
    SHAPE ABUTMENT ;
    PORT
      LAYER metal2 ;
      RECT 106.555 216.790 106.625 217.000 ;
    END
  END r0_rd_out[186]
  PIN r0_rd_out[187]
    DIRECTION OUTPUT ;
    USE SIGNAL ;
    SHAPE ABUTMENT ;
    PORT
      LAYER metal2 ;
      RECT 107.125 216.790 107.195 217.000 ;
    END
  END r0_rd_out[187]
  PIN r0_rd_out[188]
    DIRECTION OUTPUT ;
    USE SIGNAL ;
    SHAPE ABUTMENT ;
    PORT
      LAYER metal2 ;
      RECT 107.695 216.790 107.765 217.000 ;
    END
  END r0_rd_out[188]
  PIN r0_rd_out[189]
    DIRECTION OUTPUT ;
    USE SIGNAL ;
    SHAPE ABUTMENT ;
    PORT
      LAYER metal2 ;
      RECT 108.265 216.790 108.335 217.000 ;
    END
  END r0_rd_out[189]
  PIN r0_rd_out[190]
    DIRECTION OUTPUT ;
    USE SIGNAL ;
    SHAPE ABUTMENT ;
    PORT
      LAYER metal2 ;
      RECT 108.835 216.790 108.905 217.000 ;
    END
  END r0_rd_out[190]
  PIN r0_rd_out[191]
    DIRECTION OUTPUT ;
    USE SIGNAL ;
    SHAPE ABUTMENT ;
    PORT
      LAYER metal2 ;
      RECT 109.405 216.790 109.475 217.000 ;
    END
  END r0_rd_out[191]
  PIN r0_rd_out[192]
    DIRECTION OUTPUT ;
    USE SIGNAL ;
    SHAPE ABUTMENT ;
    PORT
      LAYER metal2 ;
      RECT 109.975 216.790 110.045 217.000 ;
    END
  END r0_rd_out[192]
  PIN w0_addr_in[0]
    DIRECTION INPUT ;
    USE SIGNAL ;
    SHAPE ABUTMENT ;
    PORT
      LAYER metal3 ;
      RECT 0.000 206.605 0.210 206.675 ;
    END
  END w0_addr_in[0]
  PIN w0_addr_in[1]
    DIRECTION INPUT ;
    USE SIGNAL ;
    SHAPE ABUTMENT ;
    PORT
      LAYER metal3 ;
      RECT 0.000 208.705 0.210 208.775 ;
    END
  END w0_addr_in[1]
  PIN w0_addr_in[2]
    DIRECTION INPUT ;
    USE SIGNAL ;
    SHAPE ABUTMENT ;
    PORT
      LAYER metal3 ;
      RECT 0.000 210.805 0.210 210.875 ;
    END
  END w0_addr_in[2]
  PIN w0_addr_in[3]
    DIRECTION INPUT ;
    USE SIGNAL ;
    SHAPE ABUTMENT ;
    PORT
      LAYER metal3 ;
      RECT 122.910 202.405 123.120 202.475 ;
    END
  END w0_addr_in[3]
  PIN r0_addr_in[0]
    DIRECTION INPUT ;
    USE SIGNAL ;
    SHAPE ABUTMENT ;
    PORT
      LAYER metal3 ;
      RECT 0.000 212.905 0.210 212.975 ;
    END
  END r0_addr_in[0]
  PIN r0_addr_in[1]
    DIRECTION INPUT ;
    USE SIGNAL ;
    SHAPE ABUTMENT ;
    PORT
      LAYER metal3 ;
      RECT 0.000 215.005 0.210 215.075 ;
    END
  END r0_addr_in[1]
  PIN r0_addr_in[2]
    DIRECTION INPUT ;
    USE SIGNAL ;
    SHAPE ABUTMENT ;
    PORT
      LAYER metal3 ;
      RECT 0.000 217.105 0.210 217.175 ;
    END
  END r0_addr_in[2]
  PIN r0_addr_in[3]
    DIRECTION INPUT ;
    USE SIGNAL ;
    SHAPE ABUTMENT ;
    PORT
      LAYER metal3 ;
      RECT 122.910 206.605 123.120 206.675 ;
    END
  END r0_addr_in[3]
  PIN w0_we_in
    DIRECTION INPUT ;
    USE SIGNAL ;
    SHAPE ABUTMENT ;
    PORT
      LAYER metal2 ;
      RECT 110.545 216.790 110.615 217.000 ;
    END
  END w0_we_in
  PIN w0_ce_in
    DIRECTION INPUT ;
    USE SIGNAL ;
    SHAPE ABUTMENT ;
    PORT
      LAYER metal2 ;
      RECT 111.115 216.790 111.185 217.000 ;
    END
  END w0_ce_in
  PIN w0_clk
    DIRECTION INPUT ;
    USE SIGNAL ;
    SHAPE ABUTMENT ;
    PORT
      LAYER metal2 ;
      RECT 111.685 216.790 111.755 217.000 ;
    END
  END w0_clk
  PIN r0_ce_in
    DIRECTION INPUT ;
    USE SIGNAL ;
    SHAPE ABUTMENT ;
    PORT
      LAYER metal2 ;
      RECT 112.255 216.790 112.325 217.000 ;
    END
  END r0_ce_in
  PIN r0_clk
    DIRECTION INPUT ;
    USE SIGNAL ;
    SHAPE ABUTMENT ;
    PORT
      LAYER metal2 ;
      RECT 112.825 216.790 112.895 217.000 ;
    END
  END r0_clk
  PIN VSS
    DIRECTION INOUT ;
    USE GROUND ;
    PORT
      LAYER metal4 ;
      RECT 1.000 0.840 1.280 216.160 ;
      RECT 3.240 0.840 3.520 216.160 ;
      RECT 5.480 0.840 5.760 216.160 ;
      RECT 7.720 0.840 8.000 216.160 ;
      RECT 9.960 0.840 10.240 216.160 ;
      RECT 12.200 0.840 12.480 216.160 ;
      RECT 14.440 0.840 14.720 216.160 ;
      RECT 16.680 0.840 16.960 216.160 ;
      RECT 18.920 0.840 19.200 216.160 ;
      RECT 21.160 0.840 21.440 216.160 ;
      RECT 23.400 0.840 23.680 216.160 ;
      RECT 25.640 0.840 25.920 216.160 ;
      RECT 27.880 0.840 28.160 216.160 ;
      RECT 30.120 0.840 30.400 216.160 ;
      RECT 32.360 0.840 32.640 216.160 ;
      RECT 34.600 0.840 34.880 216.160 ;
      RECT 36.840 0.840 37.120 216.160 ;
      RECT 39.080 0.840 39.360 216.160 ;
      RECT 41.320 0.840 41.600 216.160 ;
      RECT 43.560 0.840 43.840 216.160 ;
      RECT 45.800 0.840 46.080 216.160 ;
      RECT 48.040 0.840 48.320 216.160 ;
      RECT 50.280 0.840 50.560 216.160 ;
      RECT 52.520 0.840 52.800 216.160 ;
      RECT 54.760 0.840 55.040 216.160 ;
      RECT 57.000 0.840 57.280 216.160 ;
      RECT 59.240 0.840 59.520 216.160 ;
      RECT 61.480 0.840 61.760 216.160 ;
      RECT 63.720 0.840 64.000 216.160 ;
      RECT 65.960 0.840 66.240 216.160 ;
      RECT 68.200 0.840 68.480 216.160 ;
      RECT 70.440 0.840 70.720 216.160 ;
      RECT 72.680 0.840 72.960 216.160 ;
      RECT 74.920 0.840 75.200 216.160 ;
      RECT 77.160 0.840 77.440 216.160 ;
      RECT 79.400 0.840 79.680 216.160 ;
      RECT 81.640 0.840 81.920 216.160 ;
      RECT 83.880 0.840 84.160 216.160 ;
      RECT 86.120 0.840 86.400 216.160 ;
      RECT 88.360 0.840 88.640 216.160 ;
      RECT 90.600 0.840 90.880 216.160 ;
      RECT 92.840 0.840 93.120 216.160 ;
      RECT 95.080 0.840 95.360 216.160 ;
      RECT 97.320 0.840 97.600 216.160 ;
      RECT 99.560 0.840 99.840 216.160 ;
      RECT 101.800 0.840 102.080 216.160 ;
      RECT 104.040 0.840 104.320 216.160 ;
      RECT 106.280 0.840 106.560 216.160 ;
      RECT 108.520 0.840 108.800 216.160 ;
      RECT 110.760 0.840 111.040 216.160 ;
      RECT 113.000 0.840 113.280 216.160 ;
      RECT 115.240 0.840 115.520 216.160 ;
      RECT 117.480 0.840 117.760 216.160 ;
      RECT 119.720 0.840 120.000 216.160 ;
      RECT 121.960 0.840 122.240 216.160 ;
    END
  END VSS
  PIN VDD
    DIRECTION INOUT ;
    USE POWER ;
    PORT
      LAYER metal4 ;
      RECT 1.000 0.840 1.280 216.160 ;
      RECT 3.240 0.840 3.520 216.160 ;
      RECT 5.480 0.840 5.760 216.160 ;
      RECT 7.720 0.840 8.000 216.160 ;
      RECT 9.960 0.840 10.240 216.160 ;
      RECT 12.200 0.840 12.480 216.160 ;
      RECT 14.440 0.840 14.720 216.160 ;
      RECT 16.680 0.840 16.960 216.160 ;
      RECT 18.920 0.840 19.200 216.160 ;
      RECT 21.160 0.840 21.440 216.160 ;
      RECT 23.400 0.840 23.680 216.160 ;
      RECT 25.640 0.840 25.920 216.160 ;
      RECT 27.880 0.840 28.160 216.160 ;
      RECT 30.120 0.840 30.400 216.160 ;
      RECT 32.360 0.840 32.640 216.160 ;
      RECT 34.600 0.840 34.880 216.160 ;
      RECT 36.840 0.840 37.120 216.160 ;
      RECT 39.080 0.840 39.360 216.160 ;
      RECT 41.320 0.840 41.600 216.160 ;
      RECT 43.560 0.840 43.840 216.160 ;
      RECT 45.800 0.840 46.080 216.160 ;
      RECT 48.040 0.840 48.320 216.160 ;
      RECT 50.280 0.840 50.560 216.160 ;
      RECT 52.520 0.840 52.800 216.160 ;
      RECT 54.760 0.840 55.040 216.160 ;
      RECT 57.000 0.840 57.280 216.160 ;
      RECT 59.240 0.840 59.520 216.160 ;
      RECT 61.480 0.840 61.760 216.160 ;
      RECT 63.720 0.840 64.000 216.160 ;
      RECT 65.960 0.840 66.240 216.160 ;
      RECT 68.200 0.840 68.480 216.160 ;
      RECT 70.440 0.840 70.720 216.160 ;
      RECT 72.680 0.840 72.960 216.160 ;
      RECT 74.920 0.840 75.200 216.160 ;
      RECT 77.160 0.840 77.440 216.160 ;
      RECT 79.400 0.840 79.680 216.160 ;
      RECT 81.640 0.840 81.920 216.160 ;
      RECT 83.880 0.840 84.160 216.160 ;
      RECT 86.120 0.840 86.400 216.160 ;
      RECT 88.360 0.840 88.640 216.160 ;
      RECT 90.600 0.840 90.880 216.160 ;
      RECT 92.840 0.840 93.120 216.160 ;
      RECT 95.080 0.840 95.360 216.160 ;
      RECT 97.320 0.840 97.600 216.160 ;
      RECT 99.560 0.840 99.840 216.160 ;
      RECT 101.800 0.840 102.080 216.160 ;
      RECT 104.040 0.840 104.320 216.160 ;
      RECT 106.280 0.840 106.560 216.160 ;
      RECT 108.520 0.840 108.800 216.160 ;
      RECT 110.760 0.840 111.040 216.160 ;
      RECT 113.000 0.840 113.280 216.160 ;
      RECT 115.240 0.840 115.520 216.160 ;
      RECT 117.480 0.840 117.760 216.160 ;
      RECT 119.720 0.840 120.000 216.160 ;
      RECT 121.960 0.840 122.240 216.160 ;
    END
  END VDD
  OBS
    LAYER metal1 ;
    RECT 0 0 123.120 217.000 ;
    LAYER metal2 ;
    RECT 0 0 123.120 217.000 ;
    LAYER metal3 ;
    RECT 0 0 123.120 217.000 ;
    LAYER metal4 ;
    RECT 0 0 123.120 217.000 ;
    LAYER OVERLAP ;
    RECT 0 0 123.120 217.000 ;
  END
END fakeram_193x16_1r1w

END LIBRARY
